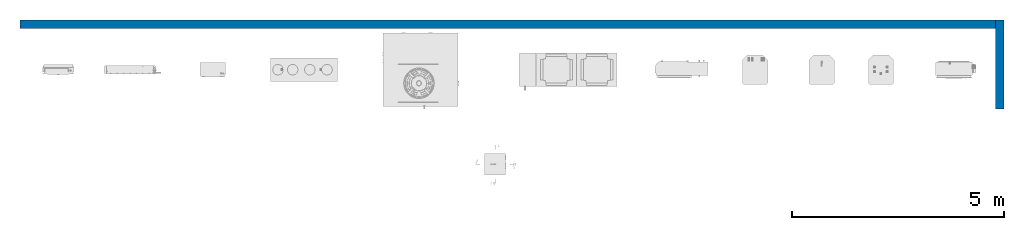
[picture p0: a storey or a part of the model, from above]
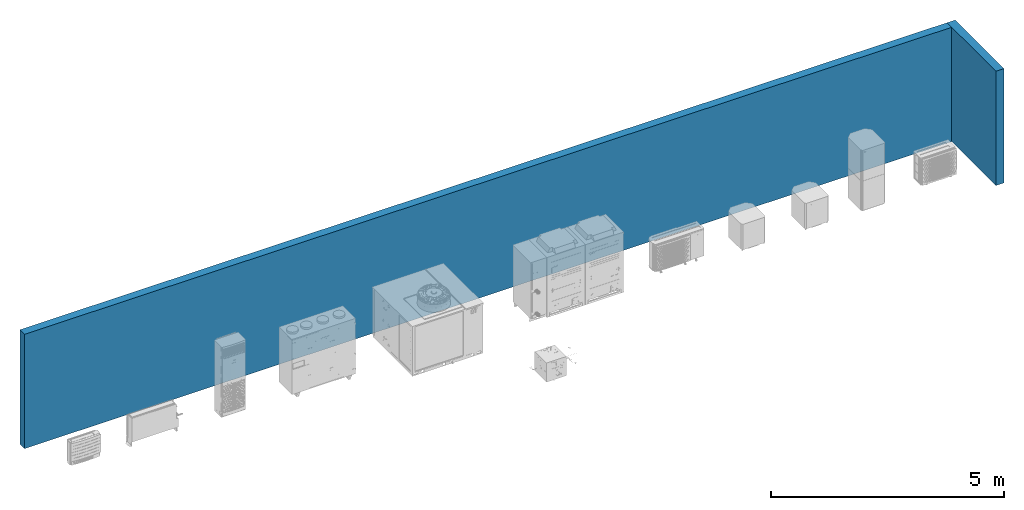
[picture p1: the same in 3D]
Properties of the parts of a building model (IFC2X3), part 1 of 2

# File
Description: ViewDefinition [CoordinationView_V2.0]
Time: 2023-03-29T12:23:34
Written by: The EXPRESS Data Manager Version 5.02.0100.07 : 28 Aug 2013
Made in: 20220224_1700(x64) - Exporter 19.2.60.3 - Default UI
Comment: STEP Physical File produced by: The EXPRESS Data Manager Version 5.02.0100.07 : 28 Aug 2013 * Module: EDMstepFileFactory/EDMstandAlone * Creation date: Wed Mar 29 12:23:34 2023 * Host: DESKTOP-IHH7OF8 * Database: C:\Users\BMP_02\AppData\Local\Temp\{1E1F3719-2578-4ED5-A2A8-9CAE0F05E7C7}\ifc * Database version: 5507 * Database creation date: Wed Mar 29 12:23:26 2023 * Schema: IFC2X3 * Model: DataRepository.ifc * Model creation date: Wed Mar 29 12:23:28 2023 * Header model: DataRepository.ifc_HeaderModel * Header model creation date: Wed Mar 29 12:23:28 2023 * EDMuser: sdai-user * EDMgroup: sdai-group * License ID and type: 5605 : Permanent license. Expiry date: * EDMstepFileFactory options: 020000

# IfcSite, Default
RefLatitude: 42, 24, 53, 508911; RefLongitude: -71, -15, -29, -58837; RefElevation: 0 mm
Other - Category: Project Information

# IfcBuilding
Pset_BuildingCommon - NumberOfStoreys: 1
Other - Category: Project Information

# IfcBuildingStorey, Level 1
LongName: Level 1; Elevation: 0 mm
Other(Type) - Category: Levels; Family Name: Level
Identity Data(Type) - Type Name: Level 1
Graphics(Type) - Color: 0; Line Pattern: Solid; Line Weight: 1; Symbol at End 1 Default: no; Symbol at End 2 Default: yes
Constraints(Type) - Elevation Base: Project Base Point
Constraints - Elevation: 0 mm
Dimensions - Computation Height: 0 mm
Identity Data - Structural: no; Building Story: yes; Name: Level 1
Other - Category: Levels; Family: Level: Level 1; Family and Type: Level: Level 1; Type: Level: Level 1; Type Id: Level: Level 1

# IfcBuildingElementProxy: reference geometry_gen, RSen_00_GM_FB_reference geometry_gen_witas:reference geometry_gen:1430872
In: Level 1
Type - Material: RSen_x_rgb 255 128 128 T80 red_gen, RSen_x_rgb 255 0 0 T00 red_gen, RSen_x_rgb 255 255 255 T00 pure white_gen, RSen_x_rgb 000 000 000 T00 black_gen, RSen_x_rgb 021 107 182 T00 blue_gen, RSen_x_rgb 000 128 000 T80 green_gen
Type - Constraints - Default Elevation: 0 mm; WT_H Reference_angled wall mounted: angled wall mounted_gen; WT_H Reference_parallel wall mounted: parallel wall mounted_gen; WT_H Reference_pendant - horizontal mounted: pendant - horizontal mounted_gen; WT_H Reference_pendant - vertical mounted: pendant - vertical mounted_gen; WT_H Reference_recessed: recessed_gen; WT_H Reference_wall mounted: wall mounted_gen
Type - Identity Data - Type Name: reference geometry_gen; WT_I Coding: V4.0; WT_I Interface: V4.0
Type - Other - Category: Generic Models; Family Name: RSen_00_GM_FB_reference geometry_gen_witas
Type - Text - 250: 250 mm; WT_I Revit manual: http://revit-mep-be-localiser.blogspot.com/2010/01/referentiebalk.html
Pset_BuildingElementProxyCommon - Reference: reference geometry_gen
Constraints - Elevation: 0 mm; Level: Level: Level 1; Host: Level : Level 1; WT_H Depth 1: 500 mm; WT_H Depth 2: 10000 mm; WT_H Half height: 250 mm; WT_H Half height_negative: -250 mm; WT_H Half length: 250 mm; WT_H Half length_negative: -250 mm; WT_H Height: 500 mm; WT_H Length: 500 mm; WT_H Reference_type: wall mounted_gen; WT_H Suspension: no; WT_H Suspension_height: 0 mm; WT_H X coordinate in plane: 0 mm; WT_H Y coordinate in plane: 0 mm
Construction - WT_V Angled wall mounted: no; WT_V Parallel wall mounted: no; WT_V Pendant - horizontal mounted: no; WT_V Pendant - vertical mounted: no; WT_V Plane: 1; WT_V Recess depth: 0 mm; WT_V Recessed: no; WT_V Rotation about axis: 0 deg; WT_V Surface mounted: yes; WT_V Suspension_height: 0 mm; WT_V X coordinate in plane: 0 mm; WT_V Y coordinate in plane: 0 mm; WT_V Z coordinate in plane: 0.1 mm
Dimensions - Area: 2.52812 m2; Volume: 0.375224 m3
Graphics - Mark: no
Other - Schedule Level: Level: Level 1; Family: RSen_00_GM_FB_reference geometry_gen_witas: reference geometry_gen; Family and Type: RSen_00_GM_FB_reference geometry_gen_witas: reference geometry_gen; Type: RSen_00_GM_FB_reference geometry_gen_witas: reference geometry_gen; Type Id: RSen_00_GM_FB_reference geometry_gen_witas: reference geometry_gen
Phasing - Phase Created: New Construction
Text - Dim_01: L; Dim_02: H; Dim_03: W

# IfcBuildingElementProxy: standard, RSen_57_ME_FB_SOg - uatyq20abay1 - SH_daikin_tbq:standard:1710730
In: Level 1
Type - Material: RSen_n6_PE_black, RSen_x_rgb 202 196 176 T00 silk gray_gen, RSen_x_rgb 055 053 053 T00 gray_gen, RSen_x_rgb 000 163 228 T00 blue_gen, RSen_x_rgb 079 201 245 T00 blue_gen, RSen_x_rgb 0 0 0 T30 aluminium rectangular canvas_gen
Type - Constraints - Default Elevation: 0 mm; TBQ SOg: yes
Type - Dimensions - TBQ Height: 1600 mm; TBQ Length: 1790 mm; TBQ Width: 1730 mm
Type - Identity Data - Manufacturer: Daikin Europe N.V.; Type Name: standard
Type - Materials and Finishes - TBQ Material 01: RSen_x_rgb 202 196 176 T00 silk gray_gen; TBQ Material 02: RSen_n6_PE_black; TBQ Material 03: RSen_x_rgb 0 0 0 T30 aluminium rectangular canvas_gen
Type - Other - Category: Mechanical Equipment; Family Name: RSen_57_ME_FB_SOg - uatyq20abay1 - SH_daikin_tbq
Pset_BuildingElementProxyCommon - Reference: standard
Pset_ManufacturerTypeInformation - Manufacturer: Daikin Europe N.V.
Constraints - Moves With Nearby Elements: no
Dimensions - Area: 14.7374 m2; Volume: 3.49974 m3
Identity Data - Mark: 110
Other - Family: RSen_57_ME_FB_SOg - uatyq20abay1 - SH_daikin_tbq: standard; Family and Type: RSen_57_ME_FB_SOg - uatyq20abay1 - SH_daikin_tbq: standard; Type: RSen_57_ME_FB_SOg - uatyq20abay1 - SH_daikin_tbq: standard; Type Id: RSen_57_ME_FB_SOg - uatyq20abay1 - SH_daikin_tbq: standard
Phasing - Phase Created: New Construction

# IfcBuildingElementProxy: standard, RSen_55_ME_FB_SOg - ewya008d2v3p - SH_daikin_tbq:standard:1500545
In: Level 1
Type - Material: RSen_x_rgb 000 163 228 T00 blue_gen, RSen_x_rgb 079 201 245 T00 blue_gen, RSen_x_rgb 055 053 053 T00 gray_gen, RSen_x_rgb 195 195 195 T00 silver_gen, RSen_x_rgb 255 255 255 T00 pure white_gen
Type - Constraints - Default Elevation: 1219.2 mm; TBQ SOg: yes
Type - Dimensions - TBQ Height: 770 mm; TBQ Length: 1245 mm; TBQ Width: 396 mm
Type - Identity Data - Manufacturer: Daikin Europe N.V.; Type Name: standard
Type - Materials and Finishes - TBQ Material 01: RSen_x_rgb 255 255 255 T00 pure white_gen; TBQ Material 02: RSen_x_rgb 195 195 195 T00 silver_gen
Type - Other - Category: Mechanical Equipment; Family Name: RSen_55_ME_FB_SOg - ewya008d2v3p - SH_daikin_tbq
Pset_BuildingElementProxyCommon - Reference: standard
Pset_ManufacturerTypeInformation - Manufacturer: Daikin Europe N.V.
Constraints - Moves With Nearby Elements: no
Dimensions - Area: 3.1003 m2; Volume: 0.285794 m3
Identity Data - Mark: 102
Other - Family: RSen_55_ME_FB_SOg - ewya008d2v3p - SH_daikin_tbq: standard; Family and Type: RSen_55_ME_FB_SOg - ewya008d2v3p - SH_daikin_tbq: standard; Type: RSen_55_ME_FB_SOg - ewya008d2v3p - SH_daikin_tbq: standard; Type Id: RSen_55_ME_FB_SOg - ewya008d2v3p - SH_daikin_tbq: standard
Phasing - Phase Created: New Construction

# IfcBuildingElementProxy: standard, RSen_55_ME_FB_SOg - ewyq050bawn - service panel hydro module - SH_daikin_tbq:standard:1500450
In: Level 1
Type - Material: RSen_x_rgb 000 163 228 T00 blue_gen, RSen_x_rgb 079 201 245 T00 blue_gen, RSen_x_rgb 055 053 053 T00 gray_gen, RSen_x_rgb 202 196 176 T00 silk gray_gen
Type - Constraints - Default Elevation: 1219.2 mm; TBQ SOg: yes
Type - Construction - TBQ Isolator switch_width: 48 mm
Type - Dimensions - TBQ Depth: 780 mm; TBQ Height: 1578 mm; TBQ Width: 448 mm
Type - Identity Data - Manufacturer: Daikin Europe N.V.; Type Name: standard
Type - Materials and Finishes - TBQ Material: RSen_x_rgb 202 196 176 T00 silk gray_gen
Type - Other - Category: Mechanical Equipment; Family Name: RSen_55_ME_FB_SOg - ewyq050bawn - service panel hydro module - SH_daikin_tbq
Pset_BuildingElementProxyCommon - Reference: standard
Pset_ManufacturerTypeInformation - Manufacturer: Daikin Europe N.V.
Constraints - Moves With Nearby Elements: no
Dimensions - Area: 2.51164 m2; Volume: 0.459061 m3
Identity Data - Mark: 99
Other - Family: RSen_55_ME_FB_SOg - ewyq050bawn - service panel hydro module - SH_daikin_tbq: standard; Family and Type: RSen_55_ME_FB_SOg - ewyq050bawn - service panel hydro module - SH_daikin_tbq: standard; Type: RSen_55_ME_FB_SOg - ewyq050bawn - service panel hydro module - SH_daikin_tbq: standard; Type Id: RSen_55_ME_FB_SOg - ewyq050bawn - service panel hydro module - SH_daikin_tbq: standard
Phasing - Phase Created: New Construction

# IfcBuildingElementProxy: standard (2)
In: Level 1
Type - Material: RSen_x_rgb 000 163 228 T00 blue_gen, RSen_x_rgb 079 201 245 T00 blue_gen, RSen_x_rgb 055 053 053 T00 gray_gen, RSen_x_rgb 202 196 176 T00 silk gray_gen, RSen_x_rgb 0 0 0 T30 aluminium rectangular canvas_gen
Type - Constraints - Default Elevation: 1219.2 mm; TBQ SOg: yes
Type - Dimensions - TBQ Depth: 780 mm; TBQ Height: 1684 mm; TBQ Width: 955 mm
Type - Identity Data - Manufacturer: Daikin Europe N.V.; Type Name: standard
Type - Materials and Finishes - TBQ Material 01: RSen_x_rgb 202 196 176 T00 silk gray_gen; TBQ Material 02: RSen_x_rgb 0 0 0 T30 aluminium rectangular canvas_gen
Type - Other - Category: Mechanical Equipment; Family Name: RSen_55_ME_FB_SOg - ewyq050bawn - service panel outdoor module - SH_daikin_tbq
Pset_BuildingElementProxyCommon - Reference: standard
Pset_ManufacturerTypeInformation - Manufacturer: Daikin Europe N.V.
Constraints - Moves With Nearby Elements: no
Dimensions - Area: 7.72265 m2; Volume: 0.180782 m3
Other - Family: RSen_55_ME_FB_SOg - ewyq050bawn - service panel outdoor module - SH_daikin_tbq: standard; Family and Type: RSen_55_ME_FB_SOg - ewyq050bawn - service panel outdoor module - SH_daikin_tbq: standard; Type: RSen_55_ME_FB_SOg - ewyq050bawn - service panel outdoor module - SH_daikin_tbq: standard; Type Id: RSen_55_ME_FB_SOg - ewyq050bawn - service panel outdoor module - SH_daikin_tbq: standard
Phasing - Phase Created: New Construction
Name (RSen_55_ME_FB_SOg - ewyq050bawn - service panel outdoor module - SH_daikin_tbq:standard:...) | Mark
1500451 | 100
1500452 | 101

# IfcBuildingElementProxy: standard, RSen_53_ME_FB_SOg - hxhd125a8v1b - SH_daikin_tbq:standard:1431638
In: Level 1
Type - Material: RSen_x_rgb 000 163 228 T00 blue_gen, RSen_x_rgb 079 201 245 T00 blue_gen, RSen_x_rgb 055 053 053 T00 gray_gen, RSen_x_rgb 224 223 219 T00 stainless steel_gen
Type - Constraints - Default Elevation: 1219.2 mm; TBQ SOg: yes
Type - Dimensions - TBQ Height: 708 mm; TBQ Length: 600 mm; TBQ Width: 694 mm
Type - Identity Data - Manufacturer: Daikin Europe N.V.; Type Name: standard
Type - Materials and Finishes - TBQ Material 01: RSen_x_rgb 224 223 219 T00 stainless steel_gen; TBQ Material 02: RSen_x_rgb 055 053 053 T00 gray_gen
Type - Other - Category: Mechanical Equipment; Family Name: RSen_53_ME_FB_SOg - hxhd125a8v1b - SH_daikin_tbq
Pset_BuildingElementProxyCommon - Reference: standard
Pset_ManufacturerTypeInformation - Manufacturer: Daikin Europe N.V.
Constraints - Moves With Nearby Elements: no; Host: Level : Level 1
Dimensions - Area: 2.24688 m2; Volume: 0.278093 m3
Identity Data - Mark: 93
Other - Family: RSen_53_ME_FB_SOg - hxhd125a8v1b - SH_daikin_tbq: standard; Family and Type: RSen_53_ME_FB_SOg - hxhd125a8v1b - SH_daikin_tbq: standard; Type: RSen_53_ME_FB_SOg - hxhd125a8v1b - SH_daikin_tbq: standard; Type Id: RSen_53_ME_FB_SOg - hxhd125a8v1b - SH_daikin_tbq: standard
Phasing - Phase Created: New Construction

# IfcBuildingElementProxy: standard, RSen_55_ME_FB_SOg - ekhbrd016ady17 - SH_daikin_tbq:standard:2643349
In: Level 1
Type - Material: RSen_x_rgb 000 163 228 T00 blue_gen, RSen_x_rgb 079 201 245 T00 blue_gen, RSen_x_rgb 055 053 053 T00 gray_gen, RSen_x_rgb 224 223 219 T00 stainless steel_gen
Type - Constraints - Default Elevation: 1219.2 mm; TBQ SOg: yes
Type - Dimensions - TBQ Height: 708 mm; TBQ Length: 600 mm; TBQ Width: 694 mm
Type - Identity Data - Manufacturer: Daikin Europe N.V.; Type Name: standard
Type - Materials and Finishes - TBQ Material 01: RSen_x_rgb 224 223 219 T00 stainless steel_gen; TBQ Material 02: RSen_x_rgb 055 053 053 T00 gray_gen
Type - Other - Category: Mechanical Equipment; Family Name: RSen_55_ME_FB_SOg - ekhbrd016ady17 - SH_daikin_tbq
Pset_BuildingElementProxyCommon - Reference: standard
Pset_ManufacturerTypeInformation - Manufacturer: Daikin Europe N.V.
Constraints - Moves With Nearby Elements: no
Dimensions - Area: 2.24688 m2; Volume: 0.278093 m3
Identity Data - Mark: 163
Other - Family: RSen_55_ME_FB_SOg - ekhbrd016ady17 - SH_daikin_tbq: standard; Family and Type: RSen_55_ME_FB_SOg - ekhbrd016ady17 - SH_daikin_tbq: standard; Type: RSen_55_ME_FB_SOg - ekhbrd016ady17 - SH_daikin_tbq: standard; Type Id: RSen_55_ME_FB_SOg - ekhbrd016ady17 - SH_daikin_tbq: standard
Phasing - Phase Created: New Construction

# IfcBuildingElementProxy: standard, RSen_53_ME_FB_SOg - ekhtsu260ac - SH_daikin_tbq:standard:1431418
In: Level 1
Type - Material: RSen_x_rgb 000 163 228 T00 blue_gen, RSen_x_rgb 079 201 245 T00 blue_gen, RSen_x_rgb 055 053 053 T00 gray_gen, RSen_x_rgb 224 223 219 T00 stainless steel_gen
Type - Constraints - Default Elevation: 1219.2 mm; TBQ SOg: yes
Type - Identity Data - Manufacturer: Daikin Europe N.V.; Type Name: standard
Type - Other - Category: Mechanical Equipment; Family Name: RSen_53_ME_FB_SOg - ekhtsu260ac - SH_daikin_tbq
Pset_BuildingElementProxyCommon - Reference: standard
Pset_ManufacturerTypeInformation - Manufacturer: Daikin Europe N.V.
Constraints - Moves With Nearby Elements: no
Dimensions - Area: 8.64187 m2; TBQ Height: 1610 mm; TBQ Length: 600 mm; TBQ Width: 694 mm; Volume: 0.537493 m3
Identity Data - Mark: 91
Materials and Finishes - TBQ Material: RSen_x_rgb 224 223 219 T00 stainless steel_gen
Other - Family: RSen_53_ME_FB_SOg - ekhtsu260ac - SH_daikin_tbq: standard; Family and Type: RSen_53_ME_FB_SOg - ekhtsu260ac - SH_daikin_tbq: standard; Type: RSen_53_ME_FB_SOg - ekhtsu260ac - SH_daikin_tbq: standard; Type Id: RSen_53_ME_FB_SOg - ekhtsu260ac - SH_daikin_tbq: standard
Phasing - Phase Created: New Construction

# IfcBuildingElementProxy: standard, RSen_57_ME_FB_SOg - atb03rasnadbt00 - SH_daikin_tbq:standard:1750596
In: Level 1
Type - Material: RSen_x_rgb 000 163 228 T00 blue_gen, RSen_x_rgb 079 201 245 T00 blue_gen, RSen_x_rgb 055 053 053 T00 gray_gen, RSen_x_rgb 255 255 255 T00 pure white_gen, RSen_x_rgb 197 197 197 T00 chrome steel_gen, RSen_x_rgb 000 000 000 T00 black_gen
Type - Constraints - Default Elevation: 1219.2 mm; TBQ SOg: yes
Type - Dimensions - TBQ Height: 1550 mm; TBQ Length: 1580 mm; TBQ Width: 550 mm
Type - Identity Data - Manufacturer: Daikin Europe N.V.; Type Name: standard
Type - Materials and Finishes - TBQ Material 01: RSen_x_rgb 255 255 255 T00 pure white_gen; TBQ Material 02: RSen_x_rgb 000 000 000 T00 black_gen; TBQ Material 03: RSen_x_rgb 197 197 197 T00 chrome steel_gen
Type - Other - Category: Mechanical Equipment; Family Name: RSen_57_ME_FB_SOg - atb03rasnadbt00 - SH_daikin_tbq
Pset_BuildingElementProxyCommon - Reference: standard
Pset_ManufacturerTypeInformation - Manufacturer: Daikin Europe N.V.
Constraints - Moves With Nearby Elements: no
Dimensions - Area: 9.99702 m2; Volume: 1.25806 m3
Identity Data - Mark: 114
Other - Family: RSen_57_ME_FB_SOg - atb03rasnadbt00 - SH_daikin_tbq: standard; Family and Type: RSen_57_ME_FB_SOg - atb03rasnadbt00 - SH_daikin_tbq: standard; Type: RSen_57_ME_FB_SOg - atb03rasnadbt00 - SH_daikin_tbq: standard; Type Id: RSen_57_ME_FB_SOg - atb03rasnadbt00 - SH_daikin_tbq: standard
Phasing - Phase Created: New Construction

# IfcBuildingElementProxy: standard, RSen_55_ME_FB_SOg - ava125amve - SH_daikin_tbq:standard:2095876
In: Level 1
Type - Material: RSen_x_rgb 055 053 053 T00 gray_gen, RSen_x_rgb 249 249 249 T00 white_gen, RSen_n6_PE_black
Type - Constraints - Default Elevation: 1219.2 mm; TBQ SOg: yes
Type - Dimensions - TBQ Height: 350 mm; TBQ Length: 598 mm; TBQ Width: 1850 mm
Type - Identity Data - Manufacturer: Daikin Europe N.V.; Type Name: standard
Type - Materials and Finishes - TBQ Material 01: RSen_x_rgb 249 249 249 T00 white_gen; TBQ Material 02: RSen_n6_PE_black
Type - Other - Category: Mechanical Equipment; Family Name: RSen_55_ME_FB_SOg - ava125amve - SH_daikin_tbq
Pset_BuildingElementProxyCommon - Reference: standard
Pset_ManufacturerTypeInformation - Manufacturer: Daikin Europe N.V.
Constraints - Moves With Nearby Elements: no
Dimensions - Area: 4.40059 m2; Volume: 0.363839 m3
Identity Data - Mark: 128
Other - Family: RSen_55_ME_FB_SOg - ava125amve - SH_daikin_tbq: standard; Family and Type: RSen_55_ME_FB_SOg - ava125amve - SH_daikin_tbq: standard; Type: RSen_55_ME_FB_SOg - ava125amve - SH_daikin_tbq: standard; Type Id: RSen_55_ME_FB_SOg - ava125amve - SH_daikin_tbq: standard
Phasing - Phase Created: New Construction

# IfcBuildingElementProxy: standard, RSen_55_ME_FB_SOg - fvxm50a3v1b9 - SH_daikin_tbq:standard:2339185
In: Level 1
Type - Material: RSen_x_rgb 055 053 053 T00 gray_gen, RSen_x_rgb 255 255 255 T00 pure white_gen
Type - Constraints - Default Elevation: 1219.2 mm; TBQ SOg: yes
Type - Identity Data - Manufacturer: Daikin Europe N.V.; Type Name: standard
Type - Other - Category: Mechanical Equipment; Family Name: RSen_55_ME_FB_SOg - fvxm50a3v1b9 - SH_daikin_tbq
Pset_BuildingElementProxyCommon - Reference: standard
Pset_ManufacturerTypeInformation - Manufacturer: Daikin Europe N.V.
Constraints - Moves With Nearby Elements: no
Dimensions - Area: 1.72482 m2; TBQ Height: 600 mm; TBQ Length: 750 mm; TBQ Width: 238 mm; Volume: 0.0955584 m3
Identity Data - Mark: 146
Materials and Finishes - TBQ Material 01: RSen_x_rgb 255 255 255 T00 pure white_gen; TBQ Material 02: RSen_x_rgb 0 0 0 T30 aluminium rectangular canvas_gen
Other - Family: RSen_55_ME_FB_SOg - fvxm50a3v1b9 - SH_daikin_tbq: standard; Family and Type: RSen_55_ME_FB_SOg - fvxm50a3v1b9 - SH_daikin_tbq: standard; Type: RSen_55_ME_FB_SOg - fvxm50a3v1b9 - SH_daikin_tbq: standard; Type Id: RSen_55_ME_FB_SOg - fvxm50a3v1b9 - SH_daikin_tbq: standard
Phasing - Phase Created: New Construction

# IfcBuildingElementProxy: standard, RSen_55_ME_FB_SOg - fna60a2veb9 - SH_daikin_tbq:standard:2294291
In: Level 1
Type - Material: RSen_x_rgb 156 169 164 T00 Galvanised steel_gen, RSen_x_rgb 40 40 40 T00 canvas_gen
Type - Constraints - Default Elevation: 1219.2 mm; TBQ SOg: yes
Type - Dimensions - TBQ Height: 723 mm; TBQ Length: 1190 mm; TBQ Width: 200 mm
Type - Identity Data - Manufacturer: Daikin Europe N.V.; Type Name: standard
Type - Materials and Finishes - TBQ Material_01: RSen_x_rgb 156 169 164 T00 Galvanised steel_gen; TBQ Material_02: RSen_x_rgb 40 40 40 T00 canvas_gen
Type - Other - Category: Mechanical Equipment; Family Name: RSen_55_ME_FB_SOg - fna60a2veb9 - SH_daikin_tbq
Pset_BuildingElementProxyCommon - Reference: standard
Pset_ManufacturerTypeInformation - Manufacturer: Daikin Europe N.V.
Constraints - Moves With Nearby Elements: no
Dimensions - Area: 1.90891 m2; Volume: 0.138914 m3
Identity Data - Mark: 138
Other - Family: RSen_55_ME_FB_SOg - fna60a2veb9 - SH_daikin_tbq: standard; Family and Type: RSen_55_ME_FB_SOg - fna60a2veb9 - SH_daikin_tbq: standard; Type: RSen_55_ME_FB_SOg - fna60a2veb9 - SH_daikin_tbq: standard; Type Id: RSen_55_ME_FB_SOg - fna60a2veb9 - SH_daikin_tbq: standard
Phasing - Phase Created: New Construction

# IfcBuildingElementProxy: standard, RSen_55_ME_FB_SOg - 5mxm90a2v1b9 - SH_daikin_tbq:standard:1451970
In: Level 1
Type - Material: RSen_x_rgb 255 255 255 T00 pure white_gen
Type - Constraints - Default Elevation: 1219.2 mm; TBQ SOg: yes
Type - Dimensions - TBQ Height: 734 mm; TBQ Length: 958 mm; TBQ Width: 408 mm
Type - Identity Data - Manufacturer: Daikin Europe N.V.; Type Name: standard
Type - Materials and Finishes - TBQ Material 01: RSen_x_rgb 255 255 255 T00 pure white_gen; TBQ Material 02: RSen_x_rgb 255 255 255 T00 pure white_gen
Type - Other - Category: Mechanical Equipment; Family Name: RSen_55_ME_FB_SOg - 5mxm90a2v1b9 - SH_daikin_tbq
Pset_BuildingElementProxyCommon - Reference: standard
Pset_ManufacturerTypeInformation - Manufacturer: Daikin Europe N.V.
Constraints - Moves With Nearby Elements: no
Dimensions - Area: 3.20005 m2; Volume: 0.182351 m3
Identity Data - Mark: 94
Other - Family: RSen_55_ME_FB_SOg - 5mxm90a2v1b9 - SH_daikin_tbq: standard; Family and Type: RSen_55_ME_FB_SOg - 5mxm90a2v1b9 - SH_daikin_tbq: standard; Type: RSen_55_ME_FB_SOg - 5mxm90a2v1b9 - SH_daikin_tbq: standard; Type Id: RSen_55_ME_FB_SOg - 5mxm90a2v1b9 - SH_daikin_tbq: standard
Phasing - Phase Created: New Construction

# IfcEnergyConversionDevice: 5mxm90a2v1b9 - split_daikin_5mxm-a9, RSen_55_ME_FB_outdoor unit - split - 5 rooms_daikin:5mxm90a2v1b9 - split_daikin_5mxm-a9:1430869
In: Level 1
Type - PredefinedType: SPLITSYSTEM; Material: RSen_x_rgb 255 255 255 T00 pure white_gen
Type - Constraints - Default Elevation: 0 mm
Type - Construction - TBQen_C_diameter_type: OD; TBQen_C_diameter_type_index: 1; TBQen_C_SOg_ME_01: RSen_55_ME_FB_SOg - 5mxm90a2v1b9 - SH_daikin_tbq: standard; TBQen_C_SOg_ME_02: standard
Type - Dimensions - TBQ_I Spacing_default: 0 mm; TBQ_I Spacing_minimum: 0 mm
Type - Electrical - RSen_E_c01_apparent_power: 0 W; RSen_E_c01_current: 0 A; RSen_E_c01_division_engine: no; RSen_E_c01_load_class: Other; RSen_E_c01_number_of_poles: 1; RSen_E_c01_voltage: 230 V; TBQen_E_c01_power: 0 W; TBQen_E_c01_power_factor: 1
Type - Electrical - Loads - RSen_E_c01_apparent_power_phase_1: 0 W; RSen_E_c01_apparent_power_phase_2: 0 W; RSen_E_c01_apparent_power_phase_3: 0 W
Type - Identity Data - Description: Heat Pump; Manufacturer: Daikin Europe N.V.; Model: Split; OmniClass Number: 23.75.10.17.17.17; OmniClass Title: Heat Pumps, Heating-Cooling Function; RSen_C_code_article: 5MXM90A2V1B9; RSen_C_code_product_class: 5MXM-A9; RSen_C_content_creator: © ThorbiQ; RSen_C_content_date_changed: 14/01/2021; RSen_C_content_date_issue: 14/01/2021; RSen_C_content_provider: Daikin Europe N.V.; RSen_C_content_version: 2.0.0; RSen_C_description: Heat Pump; RSen_C_model: Split; RSen_C_revit_version: 2018; RSen_C_type: Multi model application; RSen_C_type_comments: Outdoor unit; TBQ_I BaseKeynote: -; TBQen_C_code_product: 5MXM90A9; TBQen_C_IFC_version: 2x3; TBQen_C_license: Creative Commons Attribution NoDerivs (CC-ND); TBQen_C_license_info: https://tldrlegal.com/license/creative-commons-attribution-noderivs-(cc-nd)#summary; Type Comments: Outdoor unit; Type Name: 5mxm90a2v1b9 - split_daikin_5mxm-a9; URL: www.daikineurope.com
Type - Materials and Finishes - RSen_C_material: RSen_x_rgb 255 255 255 T00 pure white_gen
Type - Mechanical - RSen_P_c11_load_value: 0
Type - Model Properties - TBQen_C_mounting_ceiling: no; TBQen_C_mounting_floor: yes; TBQen_C_mounting_wall: no
Type - Other - Category: Mechanical Equipment; Family Name: RSen_55_ME_FB_outdoor unit - split - 5 rooms_daikin; RSen_E_c01_description: c01_el; RSen_E_c02_description: c02_controls; RSen_P_c01_description: c01_liquid pipe_room A; RSen_P_c01_diameter: 6.4 mm; RSen_P_c02_description: c02_gas pipe_room A; RSen_P_c02_diameter: 9.52 mm; RSen_P_c03_description: c03_liquid pipe_room B; RSen_P_c03_diameter: 6.4 mm; RSen_P_c04_description: c04_gas pipe_room B; RSen_P_c04_diameter: 9.52 mm; RSen_P_c05_description: c05_liquid pipe_room C; RSen_P_c05_diameter: 6.4 mm; RSen_P_c06_description: c06_gas pipe_room C; RSen_P_c06_diameter: 12.7 mm; RSen_P_c07_description: c07_liquid pipe_room D; RSen_P_c07_diameter: 6.4 mm; RSen_P_c08_description: c08_gas pipe_room D; RSen_P_c08_diameter: 12.7 mm; RSen_P_c09_description: c09_liquid pipe_room E; RSen_P_c09_diameter: 6.4 mm; RSen_P_c10_description: c10_gas pipe_room E; RSen_P_c10_diameter: 15.9 mm; RSen_P_c11_description: c11_drain; RSen_P_c11_diameter: 18 mm; TBQen_E_c01_power_factor_state: Lagging; TBQen_E_c01_system_type: Power - Unbalanced; TBQen_E_c01_yes_no: yes; TBQen_E_c02_yes_no: yes; TBQen_P_c01_diameter_calc: 6.4 mm; TBQen_P_c01_flow_configuration: Calculated; TBQen_P_c01_flow_direction: Out; TBQen_P_c01_loss_method: Not Defined; TBQen_P_c01_system_classification: Hydronic Supply; TBQen_P_c01_yes_no: yes; TBQen_P_c02_diameter_calc: 9.5 mm; TBQen_P_c02_flow_configuration: Calculated; TBQen_P_c02_flow_direction: In; TBQen_P_c02_loss_method: Not Defined; TBQen_P_c02_system_classification: Hydronic Return; TBQen_P_c02_yes_no: yes; TBQen_P_c03_diameter_calc: 6.4 mm; TBQen_P_c03_flow_configuration: Calculated; TBQen_P_c03_flow_direction: Out; TBQen_P_c03_loss_method: Not Defined; TBQen_P_c03_system_classification: Hydronic Supply; TBQen_P_c03_yes_no: yes; TBQen_P_c04_diameter_calc: 9.5 mm; TBQen_P_c04_flow_configuration: Calculated; TBQen_P_c04_flow_direction: In; TBQen_P_c04_loss_method: Not Defined; TBQen_P_c04_system_classification: Hydronic Return; TBQen_P_c04_yes_no: yes; TBQen_P_c05_diameter_calc: 6.4 mm; TBQen_P_c05_flow_configuration: Calculated; TBQen_P_c05_flow_direction: Out; TBQen_P_c05_loss_method: Not Defined; TBQen_P_c05_system_classification: Hydronic Supply; TBQen_P_c05_yes_no: yes; TBQen_P_c06_diameter_calc: 12.7 mm; TBQen_P_c06_flow_configuration: Calculated; TBQen_P_c06_flow_direction: In; TBQen_P_c06_loss_method: Not Defined; TBQen_P_c06_system_classification: Hydronic Return; TBQen_P_c06_yes_no: yes; TBQen_P_c07_diameter_calc: 6.4 mm; TBQen_P_c07_flow_configuration: Calculated; TBQen_P_c07_flow_direction: Out; TBQen_P_c07_loss_method: Not Defined; TBQen_P_c07_system_classification: Hydronic Supply; TBQen_P_c07_yes_no: yes; TBQen_P_c08_diameter_calc: 12.7 mm; TBQen_P_c08_flow_configuration: Calculated; TBQen_P_c08_flow_direction: In; TBQen_P_c08_loss_method: Not Defined; TBQen_P_c08_system_classification: Hydronic Return; TBQen_P_c08_yes_no: yes; TBQen_P_c09_diameter_calc: 6.4 mm; TBQen_P_c09_flow_configuration: Calculated; TBQen_P_c09_flow_direction: Out; TBQen_P_c09_loss_method: Not Defined; TBQen_P_c09_system_classification: Hydronic Supply; TBQen_P_c09_yes_no: yes; TBQen_P_c10_diameter_calc: 15.9 mm; TBQen_P_c10_flow_configuration: Calculated; TBQen_P_c10_flow_direction: In; TBQen_P_c10_loss_method: Not Defined; TBQen_P_c10_system_classification: Hydronic Return; TBQen_P_c10_yes_no: yes; TBQen_P_c11_diameter_calc: 18 mm; TBQen_P_c11_flow_configuration: Fixture Units; TBQen_P_c11_flow_direction: Out; TBQen_P_c11_loss_method: Not Defined; TBQen_P_c11_system_classification: Sanitary; TBQen_P_c11_yes_no: yes
Pset_ManufacturerTypeInformation - Manufacturer: Daikin Europe N.V.
Pset_DistributionFlowElementCommon - Reference: 5mxm90a2v1b9 - split_daikin_5mxm-a9
Constraints - Elevation: 0 mm; Host: Level : Level 1; Level: Level: Level 1
Construction - RSen_C_mounting: On the floor; TBQen_C_alignment: Center; TBQen_C_alignment_index: 0; TBQen_C_component_02_offset: 0 mm; TBQen_C_component_03_offset: 0 mm; TBQen_C_component_04_offset: 0 mm; TBQen_C_GOg: no; TBQen_C_mounting_index: 0; TBQen_C_offset_from_base_level: 0 mm; TBQen_C_offset_from_wall: 0 mm; TBQen_C_placement: Spacing Default; TBQen_C_placement_index: 0; TBQen_C_SOg: yes
Dimensions - Area: 38.3842 m2; RSen_C_height: 734 mm; RSen_C_length: 959 mm; RSen_C_width: 391 mm; Volume: 8.07687 m3
Graphics - TBQen_C_clearance_zone: no; TBQen_C_connection_zone: no; TBQen_C_logo: no; TBQen_C_maintenance_zone: no; TBQen_C_neighbour_unit: no; TBQen_C_neighbour_unit_displacement_back: 0 mm; TBQen_C_neighbour_unit_displacement_front: 0 mm; TBQen_C_neighbour_unit_displacement_left: 0 mm; TBQen_C_neighbour_unit_displacement_right: 0 mm
Identity Data - Mark: 84
Mechanical - RSen_P_c01_volume_flow: 0 m3/s; RSen_P_c02_volume_flow: 0 m3/s; RSen_P_c03_volume_flow: 0 m3/s; RSen_P_c04_volume_flow: 0 m3/s; RSen_P_c05_volume_flow: 0 m3/s; RSen_P_c06_volume_flow: 0 m3/s; RSen_P_c07_volume_flow: 0 m3/s; RSen_P_c08_volume_flow: 0 m3/s; RSen_P_c09_volume_flow: 0 m3/s; RSen_P_c10_volume_flow: 0 m3/s; System Classification: Hydronic Supply,Hydronic Return,Power,Hydronic Supply,Hydronic Return,Hydronic Supply,Controls,Hydronic Supply,Hydronic Return,Hydronic Supply,Hydronic Return,Sanitary
Other - Family: RSen_55_ME_FB_outdoor unit - split - 5 rooms_daikin: 5mxm90a2v1b9 - split_daikin_5mxm-a9; Family and Type: RSen_55_ME_FB_outdoor unit - split - 5 rooms_daikin: 5mxm90a2v1b9 - split_daikin_5mxm-a9; Schedule Level: Level: Level 1; Type: RSen_55_ME_FB_outdoor unit - split - 5 rooms_daikin: 5mxm90a2v1b9 - split_daikin_5mxm-a9; Type Id: RSen_55_ME_FB_outdoor unit - split - 5 rooms_daikin: 5mxm90a2v1b9 - split_daikin_5mxm-a9; ZZZ_V P_c01_plane_Integer: 4; ZZZ_V P_c01_X_Length: -407.5 mm; ZZZ_V P_c01_Y_Length: 49 mm
Phasing - Phase Created: New Construction
Text - RSen_C_content_manual: https://thorbiq.freshdesk.com/support/solutions

# IfcEnergyConversionDevice: atb03rasnadbt00 - air handling unit - right_daikin_lxwxh 1580x550x1550 mm, RSen_57_ME_FB_air handling unit - modular - t_daikin:atb03rasnadbt00 - air handling unit - right_daikin_lxwxh 1580x550x1550 mm:1747841
In: Level 1
Type - PredefinedType: AIRHANDLER; Classification: 57.10.10.10 (Uniformat); Material: RSen_x_rgb 255 255 255 T00 pure white_gen
Type - Constraints - Default Elevation: 0 mm
Type - Construction - TBQen_C_diameter_type_index: 1; TBQen_C_SOg_ME_02: standard; TBQen_C_diameter_type: OD; TBQen_C_SOg_ME_01: RSen_57_ME_FB_SOg - atb03rasnadbt00 - SH_daikin_tbq: standard
Type - Dimensions - RSen_C_height: 1550 mm; RSen_C_length: 1580 mm; RSen_C_width: 550 mm
Type - Electrical - RSen_E_c01_division_engine: no; RSen_E_c01_load_class: Other; RSen_E_c01_number_of_poles: 1; TBQen_E_c01_power_factor: 1; RSen_E_c01_apparent_power: 1060 W; RSen_E_c01_current: 0 A; RSen_E_c01_voltage: 230 V; TBQen_E_c01_power: 1060 W
Type - Identity Data - Assembly Code: 57.10.10.10; Description: Ventilation; Manufacturer: Daikin Europe N.V.; Model: Modular T; OmniClass Number: 23.75.35.14; OmniClass Title: Air Handling Units; RSen_C_code_article: ATB03RASNADBT00; RSen_C_code_ETIM: Ventilation appliance; RSen_C_code_ETIM_URL: https://prod.etim-international.com/Class/Details?classId=EC000267&classVersion=5; RSen_C_code_gtin: -; RSen_C_code_product_class: ATB-S; RSen_C_content_creator: © ThorbiQ; RSen_C_content_date_changed: 14/01/2021; RSen_C_content_date_issue: 14/01/2021; RSen_C_content_provider: Daikin Europe N.V.; RSen_C_content_version: 2.0.0; RSen_C_description: Ventilation; RSen_C_model: Modular T; RSen_C_revit_version: 2018; RSen_C_type: Air handling unit - right; RSen_C_type_comments: Indoor Unit; TBQ_I BaseKeynote: 57.10.10.10; TBQen_C_code_product: ATB03RAS; TBQen_C_IFC_version: 2x3; TBQen_C_license: Creative Commons Attribution NoDerivs (CC-ND); TBQen_C_license_info: https://tldrlegal.com/license/creative-commons-attribution-noderivs-(cc-nd)#summary; Type Comments: Indoor Unit; Type Name: atb03rasnadbt00 - air handling unit - right_daikin_lxwxh 1580x550x1550 mm; URL: www.daikineurope.com
Type - Materials and Finishes - RSen_C_material: RSen_x_rgb 255 255 255 T00 pure white_gen
Type - Mechanical - RSen_P_c01_load_value: 0; RSen_P_c02_load_value: 0; TBQ_I Air flow rate_speed 1: 7.8477 m3/s; TBQ_I Air flow rate_speed 2: 0 m3/s; TBQ_I Air flow rate_speed 3: 0 m3/s
Type - Model Properties - TBQen_C_mounting_ceiling: no; TBQen_C_mounting_floor: yes; TBQen_C_mounting_wall: no
Type - Other - Category: Mechanical Equipment; TBQen_E_c01_yes_no: yes; TBQen_E_c02_yes_no: yes; TBQen_P_c01_yes_no: yes; TBQen_P_c02_yes_no: yes; TBQen_M_c01_yes_no: yes; TBQen_M_c02_yes_no: yes; Family Name: RSen_57_ME_FB_air handling unit - modular - t_daikin; RSen_E_c01_description: c01_el; RSen_E_c02_description: c02_controls; RSen_M_c01_description: c01_fresh air_outdoor; RSen_M_c01_diameter: 250 mm; RSen_M_c01_height: 0 mm; RSen_M_c01_width: 0 mm; RSen_M_c02_description: c02_exhaust air; RSen_M_c02_diameter: 250 mm; RSen_M_c02_height: 0 mm; RSen_M_c02_width: 0 mm; RSen_M_c03_description: c03_supply air; RSen_M_c03_diameter: 250 mm; RSen_M_c03_height: 0 mm; RSen_M_c03_width: 0 mm; RSen_M_c04_description: c04_return air; RSen_M_c04_diameter: 250 mm; RSen_M_c04_height: 0 mm; RSen_M_c04_width: 0 mm; RSen_P_c01_description: c01_drain piping connection; RSen_P_c01_diameter: 21.3 mm; RSen_P_c02_description: c01_drain piping connection; RSen_P_c02_diameter: 21.3 mm; TBQen_E_c01_power_factor_state: Lagging; TBQen_E_c01_system_type: Power - Balanced; TBQen_M_c01_flow_configuration: Preset; TBQen_M_c01_flow_direction: In; TBQen_M_c01_loss_method: Not Defined; TBQen_M_c01_shape: Round; TBQen_M_c01_system_classification: Supply Air; TBQen_M_c02_flow_configuration: Preset; TBQen_M_c02_flow_direction: Out; TBQen_M_c02_loss_method: Not Defined; TBQen_M_c02_shape: Round; TBQen_M_c02_system_classification: Exhaust Air; TBQen_M_c03_flow_configuration: Preset; TBQen_M_c03_flow_direction: Out; TBQen_M_c03_loss_method: Not Defined; TBQen_M_c03_shape: Round; TBQen_M_c03_system_classification: Supply Air; TBQen_M_c03_yes_no: yes; TBQen_M_c04_flow_configuration: Preset; TBQen_M_c04_flow_direction: In; TBQen_M_c04_loss_method: Not Defined; TBQen_M_c04_shape: Round; TBQen_M_c04_system_classification: Return Air; TBQen_M_c04_yes_no: yes; TBQen_P_c01_diameter_calc: 21.3 mm; TBQen_P_c01_flow_configuration: Fixture Units; TBQen_P_c01_flow_direction: Out; TBQen_P_c01_loss_method: Not Defined; TBQen_P_c01_system_classification: Sanitary; TBQen_P_c02_diameter_calc: 21.3 mm; TBQen_P_c02_flow_configuration: Fixture Units; TBQen_P_c02_flow_direction: Out; TBQen_P_c02_loss_method: Not Defined; TBQen_P_c02_system_classification: Sanitary
Pset_ManufacturerTypeInformation - Manufacturer: Daikin Europe N.V.
Pset_DistributionFlowElementCommon - Reference: atb03rasnadbt00 - air handling unit - right_daikin_lxwxh 1580x550x1550 mm
Constraints - Elevation: 0 mm; Level: Level: Level 1; Host: Level : Level 1
Construction - TBQen_C_alignment_index: 0; TBQen_C_GOg: no; TBQen_C_SOg: yes; TBQen_C_suspension_height: 0 mm; TBQen_C_alignment: Center
Dimensions - Area: 88.141 m2; Volume: 28.3056 m3
Graphics - TBQen_C_clearance_zone: no; TBQen_C_connection_zone: no; TBQen_C_logo: no; TBQen_C_maintenance_zone: no; TBQen_C_neighbour_unit: no; TBQen_C_neighbour_unit_displacement_back: 0 mm; TBQen_C_neighbour_unit_displacement_front: 0 mm; TBQen_C_neighbour_unit_displacement_left: 0 mm; TBQen_C_neighbour_unit_displacement_right: 0 mm
Identity Data - Mark: 112
Mechanical - RSen_M_c01_flow_rate: 7.8477 m3/s; RSen_M_c02_flow_rate: 7.8477 m3/s; RSen_M_c03_flow_rate: 7.8477 m3/s; RSen_M_c04_flow_rate: 7.8477 m3/s; System Classification: Sanitary,Return Air,Supply Air,Exhaust Air,Power,Controls
Mechanical - Flow - TBQen_M_flow_rate_index: 0; TBQen_M_flow_rate: 7.8477 m3/s; TBQen_M_flow_rate_info: Low
Other - Schedule Level: Level: Level 1; Family: RSen_57_ME_FB_air handling unit - modular - t_daikin: atb03rasnadbt00 - air handling unit - right_daikin_lxwxh 1580x550x1550 mm; Family and Type: RSen_57_ME_FB_air handling unit - modular - t_daikin: atb03rasnadbt00 - air handling unit - right_daikin_lxwxh 1580x550x1550 mm; Type: RSen_57_ME_FB_air handling unit - modular - t_daikin: atb03rasnadbt00 - air handling unit - right_daikin_lxwxh 1580x550x1550 mm; Type Id: RSen_57_ME_FB_air handling unit - modular - t_daikin: atb03rasnadbt00 - air handling unit - right_daikin_lxwxh 1580x550x1550 mm; ZZZ_V P_c01_plane_Integer: 2; ZZZ_V P_c01_X_Length: 524 mm; ZZZ_V P_c01_Y_Length: 0 mm
Phasing - Phase Created: New Construction
Text - RSen_C_content_manual: https://thorbiq.freshdesk.com/support/solutions

# IfcEnergyConversionDevice: ava125amve - floor standing unit_daikin_lxwxh 600x350x1850 mm, RSen_55_ME_FB_indoor unit - sky air - cassette-wall-floor_daikin:ava125amve - floor standing unit_daikin_lxwxh 600x350x1850 mm:2091445
In: Level 1
Type - PredefinedType: AIRCONDITIONINGUNIT; Material: RSen_x_rgb 255 255 255 T00 pure white_gen
Type - Constraints - Default Elevation: 0 mm
Type - Construction - TBQen_C_diameter_type_index: 1; TBQen_C_SOg_ME_02: standard; TBQen_C_accessory_01_index: 0; TBQen_C_diameter_type: OD; TBQen_C_SOg_ME_01: RSen_55_ME_FB_SOg - ava125amve - SH_daikin_tbq: standard
Type - Dimensions - RSen_C_height: 1850 mm; RSen_C_length: 600 mm; RSen_C_width: 350 mm
Type - Electrical - RSen_E_c01_division_engine: no; RSen_E_c01_load_class: Other; RSen_E_c01_number_of_poles: 1; TBQen_E_c01_power_factor: 1; RSen_E_c01_apparent_power: 0 W; RSen_E_c01_current: 0 A; RSen_E_c01_voltage: 230 V; TBQen_E_c01_power: 0 W
Type - Identity Data - Description: Floor standing; Manufacturer: Daikin Europe N.V.; Model: Sky Air; OmniClass Number: 23.75.10.24.21.27.24; OmniClass Title: Room Air Conditioners; RSen_C_code_article: AVA125AMVE; RSen_C_code_ETIM: Air-conditioning split system – inside unit (evaporator); RSen_C_code_ETIM_URL: https://prod.etim-international.com/Class/Details?classId=EC011580&classVersion=4; RSen_C_code_gtin: -; RSen_C_code_product_class: AVA-A; RSen_C_content_creator: © ThorbiQ; RSen_C_content_date_changed: 14/01/2021; RSen_C_content_date_issue: 14/01/2021; RSen_C_content_provider: Daikin Europe N.V.; RSen_C_content_version: 2.0.0; RSen_C_description: Floor standing; RSen_C_model: Sky Air; RSen_C_revit_version: 2018; RSen_C_type: Floor standing unit; RSen_C_type_comments: Indoor unit; TBQ_I BaseKeynote: 55.10.10.10; TBQen_C_code_product: AVA125A; TBQen_C_IFC_version: 2x3; TBQen_C_license: Creative Commons Attribution NoDerivs (CC-ND); TBQen_C_license_info: https://tldrlegal.com/license/creative-commons-attribution-noderivs-(cc-nd)#summary; Type Comments: Indoor unit; Type Name: ava125amve - floor standing unit_daikin_lxwxh 600x350x1850 mm; URL: www.daikineurope.com
Type - Materials and Finishes - RSen_C_material: RSen_x_rgb 255 255 255 T00 pure white_gen
Type - Mechanical - RSen_P_c01_volume_flow: 0 m3/s; RSen_P_c02_volume_flow: 0 m3/s; RSen_P_c03_load_value: 0; TBQ_I Air flow rate_speed 1: 14.1259 m3/s; TBQ_I Air flow rate_speed 2: 15.303 m3/s; TBQ_I Air flow rate_speed 3: 16.4802 m3/s; TBQ_I Fresh air_percentage intake: 0
Type - Model Properties - TBQen_C_mounting_ceiling: no; TBQen_C_mounting_floor: yes; TBQen_C_mounting_wall: no
Type - Other - Category: Mechanical Equipment; TBQen_E_c01_yes_no: yes; TBQen_E_c02_yes_no: yes; TBQen_P_c01_yes_no: yes; TBQen_P_c02_yes_no: yes; TBQen_P_c03_yes_no: yes; Family Name: RSen_55_ME_FB_indoor unit - sky air - cassette-wall-floor_daikin; RSen_E_c01_description: c01_el; RSen_E_c02_description: c02_controls; RSen_P_c01_description: c02_liquid piping connection; RSen_P_c01_diameter: 9.52 mm; RSen_P_c02_description: c03_gas piping connection; RSen_P_c02_diameter: 15.9 mm; RSen_P_c03_description: c04_drain piping connection; RSen_P_c03_diameter: 26 mm; TBQen_E_c01_power_factor_state: Lagging; TBQen_E_c01_system_type: Power - Balanced; TBQen_P_c01_diameter_calc: 9.5 mm; TBQen_P_c01_flow_configuration: Preset; TBQen_P_c01_flow_direction: In; TBQen_P_c01_loss_method: Not Defined; TBQen_P_c01_system_classification: Hydronic Supply; TBQen_P_c02_diameter_calc: 15.9 mm; TBQen_P_c02_flow_configuration: Preset; TBQen_P_c02_flow_direction: Out; TBQen_P_c02_loss_method: Not Defined; TBQen_P_c02_system_classification: Hydronic Return; TBQen_P_c03_diameter_calc: 26 mm; TBQen_P_c03_flow_configuration: Fixture Units; TBQen_P_c03_flow_direction: Out; TBQen_P_c03_loss_method: Not Defined; TBQen_P_c03_system_classification: Sanitary
Pset_ManufacturerTypeInformation - Manufacturer: Daikin Europe N.V.
Pset_DistributionFlowElementCommon - Reference: ava125amve - floor standing unit_daikin_lxwxh 600x350x1850 mm
Constraints - Elevation: 0 mm; Level: Level: Level 1; Host: Level : Level 1
Construction - TBQen_C_alignment_index: 0; TBQen_C_GOg: no; TBQen_C_SOg: yes; TBQen_C_suspension_height: 0 mm; TBQen_C_alignment: Center
Dimensions - Area: 43.4071 m2; Volume: 9.7773 m3
Graphics - TBQen_C_clearance_zone: no; TBQen_C_connection_zone: no; TBQen_C_logo: no; TBQen_C_maintenance_zone: no; TBQen_C_neighbour_unit: no; TBQen_C_neighbour_unit_displacement_back: 0 mm; TBQen_C_neighbour_unit_displacement_front: 0 mm; TBQen_C_neighbour_unit_displacement_left: 0 mm; TBQen_C_neighbour_unit_displacement_right: 0 mm
Identity Data - Mark: 127
Mechanical - System Classification: Hydronic Return,Hydronic Supply,Sanitary,Power,Controls
Mechanical - Flow - TBQen_M_flow_rate: 15.303 m3/s; TBQen_M_flow_rate_index: 1; TBQen_M_flow_rate_info: Norm.
Other - Schedule Level: Level: Level 1; ZZZ_V P_c01_plane_Integer: 2; Family: RSen_55_ME_FB_indoor unit - sky air - cassette-wall-floor_daikin: ava125amve - floor standing unit_daikin_lxwxh 600x350x1850 mm; Family and Type: RSen_55_ME_FB_indoor unit - sky air - cassette-wall-floor_daikin: ava125amve - floor standing unit_daikin_lxwxh 600x350x1850 mm; Type: RSen_55_ME_FB_indoor unit - sky air - cassette-wall-floor_daikin: ava125amve - floor standing unit_daikin_lxwxh 600x350x1850 mm; Type Id: RSen_55_ME_FB_indoor unit - sky air - cassette-wall-floor_daikin: ava125amve - floor standing unit_daikin_lxwxh 600x350x1850 mm; ZZZ_V P_c01_X_Length: -223 mm; ZZZ_V P_c01_Y_Length: -91 mm
Phasing - Phase Created: New Construction
Text - RSen_C_content_manual: https://thorbiq.freshdesk.com/support/solutions

# IfcEnergyConversionDevice: ekhbrd016ady17 - altherma high temperature_daikin_lxwxh 600x694x708 mm, RSen_53_ME_FB_indoor unit - altherma - air to water - wall mounted_daikin:ekhbrd016ady17 - altherma high temperature_daikin_lxwxh 600x694x708 mm:2641016
In: Level 1
Type - PredefinedType: AIRCONDITIONINGUNIT; Classification: 56.10.10 (Uniformat); Material: RSen_x_rgb 188 188 190 T00 gray_gen
Type - Constraints - Default Elevation: 0 mm
Type - Construction - TBQen_C_diameter_type_index: 1; TBQen_C_SOg_ME_02: standard; TBQen_C_accessory_01_index: 0; TBQen_C_diameter_type: OD; TBQen_C_SOg_ME_01: RSen_55_ME_FB_SOg - ekhbrd016ady17 - SH_daikin_tbq: standard
Type - Dimensions - RSen_C_diameter: 0 mm; RSen_C_height: 708 mm; RSen_C_length: 600 mm; RSen_C_width: 694 mm
Type - Electrical - RSen_E_c01_load_class: Other; TBQen_E_c01_power_factor: 1; RSen_E_c01_division_engine: yes; RSen_E_c01_number_of_poles: 3; RSen_E_c01_apparent_power: 0 W; RSen_E_c01_current: 0 A; RSen_E_c01_voltage: 400 V; TBQen_E_c01_power: 0 W
Type - Identity Data - Assembly Code: 56.10.10; Description: Air To Water Heat Pump; Manufacturer: Daikin Europe N.V.; Model: Altherma High temperature; OmniClass Number: 23.75.10.21.11; OmniClass Title: Air-Source Heat Pumps; RSen_C_code_article: EKHBRD016ADY17; RSen_C_code_product_class: EKHBRD-ADY17; RSen_C_content_creator: © ThorbiQ; RSen_C_content_date_changed: 14/01/2021; RSen_C_content_date_issue: 14/01/2021; RSen_C_content_provider: Daikin Europe N.V.; RSen_C_content_version: 2.0.0; RSen_C_description: Air To Water Heat Pump; RSen_C_model: Altherma High temperature; RSen_C_revit_version: 2018; RSen_C_type: Heating Only; RSen_C_type_comments: Indoor Unit; TBQ_I BaseKeynote: 56.10.10; TBQen_C_code_product: EKHBRD016ADY17; TBQen_C_data_issue_date: RSen_53_ME_FB_indoor unit - altherma - bivalent_daikin; TBQen_C_IFC_version: 2x3; TBQen_C_license: Creative Commons Attribution NoDerivs (CC-ND); TBQen_C_license_info: https://tldrlegal.com/license/creative-commons-attribution-noderivs-(cc-nd)#summary; Type Comments: Indoor Unit; Type Name: ekhbrd016ady17 - altherma high temperature_daikin_lxwxh 600x694x708 mm; URL: www.daikineurope.com
Type - Materials and Finishes - RSen_C_material: RSen_x_rgb 188 188 190 T00 gray_gen
Type - Model Properties - TBQen_C_mounting_ceiling: no; TBQen_C_mounting_floor: yes; TBQen_C_mounting_wall: no
Type - Other - Category: Mechanical Equipment; TBQen_E_c01_yes_no: yes; TBQen_E_c02_yes_no: yes; TBQen_P_c01_yes_no: yes; TBQen_P_c02_yes_no: yes; TBQen_P_c03_yes_no: yes; TBQen_P_c04_yes_no: yes; Family Name: RSen_53_ME_FB_indoor unit - altherma - air to water - wall mounted_daikin; RSen_E_c01_description: c01_el; RSen_E_c02_description: c02_controls; RSen_P_c01_description: c01_liquid connection; RSen_P_c01_diameter: 9.52 mm; RSen_P_c02_description: c02_gas connection; RSen_P_c02_diameter: 15.9 mm; RSen_P_c03_description: c03_heating in; RSen_P_c03_diameter: 25 mm; RSen_P_c04_description: c04_heating out; RSen_P_c04_diameter: 25 mm; TBQen_E_c01_power_factor_state: Lagging; TBQen_E_c01_system_type: Power - Balanced; TBQen_P_c01_diameter_calc: 9.5 mm; TBQen_P_c01_flow_configuration: Preset; TBQen_P_c01_flow_direction: In; TBQen_P_c01_loss_method: Not Defined; TBQen_P_c01_system_classification: Hydronic Supply; TBQen_P_c02_diameter_calc: 15.9 mm; TBQen_P_c02_flow_configuration: Preset; TBQen_P_c02_flow_direction: Out; TBQen_P_c02_loss_method: Not Defined; TBQen_P_c02_system_classification: Hydronic Return; TBQen_P_c03_diameter_calc: 25 mm; TBQen_P_c03_flow_configuration: Calculated; TBQen_P_c03_flow_direction: In; TBQen_P_c03_loss_method: Not Defined; TBQen_P_c03_system_classification: Hydronic Return; TBQen_P_c04_diameter_calc: 25 mm; TBQen_P_c04_flow_configuration: Calculated; TBQen_P_c04_flow_direction: Out; TBQen_P_c04_loss_method: Not Defined; TBQen_P_c04_system_classification: Hydronic Supply
Pset_ManufacturerTypeInformation - Manufacturer: Daikin Europe N.V.
Pset_DistributionFlowElementCommon - Reference: ekhbrd016ady17 - altherma high temperature_daikin_lxwxh 600x694x708 mm
Constraints - Elevation: 0 mm; Level: Level: Level 1; Host: Level : Level 1
Construction - TBQen_C_alignment_index: 0; TBQen_C_GOg: no; TBQen_C_offset_from_base_level: 0 mm; TBQen_C_SOg: yes; TBQen_C_suspension_height: 0 mm; TBQen_C_alignment: Center
Dimensions - Area: 29.6784 m2; Volume: 7.32096 m3
Graphics - TBQen_C_clearance_zone: no; TBQen_C_connection_zone: no; TBQen_C_logo: no; TBQen_C_maintenance_zone: no; TBQen_C_neighbour_unit: no; TBQen_C_neighbour_unit_displacement_back: 0 mm; TBQen_C_neighbour_unit_displacement_front: 0 mm; TBQen_C_neighbour_unit_displacement_left: 0 mm; TBQen_C_neighbour_unit_displacement_right: 0 mm
Identity Data - Mark: 162
Mechanical - RSen_P_c01_volume_flow: 0 m3/s; RSen_P_c02_volume_flow: 0 m3/s; RSen_P_c03_volume_flow: 0 m3/s; RSen_P_c04_volume_flow: 0 m3/s; System Classification: Hydronic Supply,Hydronic Return,Power,Controls,Hydronic Supply
Other - Schedule Level: Level: Level 1; ZZZ_V P_c01_plane_Integer: 4; Family: RSen_53_ME_FB_indoor unit - altherma - air to water - wall mounted_daikin: ekhbrd016ady17 - altherma high temperature_daikin_lxwxh 600x694x708 mm; Family and Type: RSen_53_ME_FB_indoor unit - altherma - air to water - wall mounted_daikin: ekhbrd016ady17 - altherma high temperature_daikin_lxwxh 600x694x708 mm; Type: RSen_53_ME_FB_indoor unit - altherma - air to water - wall mounted_daikin: ekhbrd016ady17 - altherma high temperature_daikin_lxwxh 600x694x708 mm; Type Id: RSen_53_ME_FB_indoor unit - altherma - air to water - wall mounted_daikin: ekhbrd016ady17 - altherma high temperature_daikin_lxwxh 600x694x708 mm; ZZZ_V P_c01_X_Length: 0 mm; ZZZ_V P_c01_Y_Length: 268 mm
Phasing - Phase Created: New Construction
Text - RSen_C_content_manual: https://thorbiq.freshdesk.com/support/solutions

# IfcEnergyConversionDevice: ewya008d2v3p - heat pump_daikin_ewya-dv3p, RSen_55_ME_FB_air cooled chiller_daikin:ewya008d2v3p - heat pump_daikin_ewya-dv3p:1489211
In: Level 1
Type - PredefinedType: AIRCOOLED; Classification: 55.10.10 (Uniformat); Material: RSen_x_rgb 255 255 255 T00 pure white_gen
Type - Constraints - Default Elevation: 1000 mm
Type - Construction - TBQen_C_SOg_ME_02: standard; TBQen_C_diameter_type: DN; TBQen_C_diameter_type_index: 0; TBQen_C_SOg_ME_01: RSen_55_ME_FB_SOg - ewya008d2v3p - SH_daikin_tbq: standard
Type - Dimensions - TBQ_I Spacing_default: 0 mm; TBQ_I Spacing_minimum: 0 mm
Type - Electrical - RSen_E_c01_division_engine: no; RSen_E_c01_load_class: Other; RSen_E_c01_number_of_poles: 1; TBQen_E_c01_power_factor: 1; RSen_E_c01_apparent_power: 1190 W; RSen_E_c01_current: 0 A; RSen_E_c01_voltage: 230 V; TBQen_E_c01_power: 1190 W
Type - Electrical - Loads - RSen_E_c01_apparent_power_phase_1: 396.667 W; RSen_E_c01_apparent_power_phase_2: 396.667 W; RSen_E_c01_apparent_power_phase_3: 396.667 W
Type - Identity Data - Assembly Code: 55.10.10; Description: Heat Pump; Manufacturer: Daikin Europe N.V.; Model: Chillers air cooled; OmniClass Number: 23.75.10.24.21.21; OmniClass Title: Packaged Water Chillers; RSen_C_code_article: EWYA008D2V3P; RSen_C_code_ETIM: Airco splitsysteem - multi split condensingunit luchtgekoeld; RSen_C_code_ETIM_URL: https://prod.etim-international.com/Class/Details?classId=EC011584&classVersion=2; RSen_C_code_product_class: EWYA-DV3P; RSen_C_content_creator: © ThorbiQ; RSen_C_content_date_changed: 14/01/2021; RSen_C_content_date_issue: 14/01/2021; RSen_C_content_provider: Daikin Europe N.V.; RSen_C_content_version: 2.0.0; RSen_C_description: Heat Pump; RSen_C_model: Chillers air cooled; RSen_C_revit_version: 2018; RSen_C_type: Air cooled mini inverter heat pump; RSen_C_type_comments: Single Unit; TBQ_I BaseKeynote: 55.10.10; TBQen_C_code_product: EWYA008DV3P; TBQen_C_IFC_version: 2x3; TBQen_C_license: Creative Commons Attribution NoDerivs (CC-ND); TBQen_C_license_info: https://tldrlegal.com/license/creative-commons-attribution-noderivs-(cc-nd)#summary; Type Comments: Single Unit; Type Name: ewya008d2v3p - heat pump_daikin_ewya-dv3p; URL: www.daikineurope.com
Type - Materials and Finishes - RSen_C_material: RSen_x_rgb 255 255 255 T00 pure white_gen
Type - Model Properties - TBQen_C_mounting_ceiling: no; TBQen_C_mounting_floor: yes; TBQen_C_mounting_wall: no
Type - Other - Category: Mechanical Equipment; TBQen_E_c01_yes_no: yes; TBQen_E_c02_yes_no: yes; TBQen_P_c01_yes_no: yes; TBQen_P_c02_yes_no: yes; Family Name: RSen_55_ME_FB_air cooled chiller_daikin; RSen_E_c01_description: c01_el; RSen_E_c02_description: c02_controls; RSen_P_c01_description: c01_chilled water in connection; RSen_P_c01_diameter: 25 mm; RSen_P_c02_description: c02_chilled water out connection; RSen_P_c02_diameter: 25 mm; TBQen_E_c01_power_factor_state: Lagging; TBQen_E_c01_system_type: Power - Unbalanced; TBQen_P_c01_diameter_calc: 25 mm; TBQen_P_c01_flow_configuration: Calculated; TBQen_P_c01_flow_direction: In; TBQen_P_c01_loss_method: Not Defined; TBQen_P_c01_system_classification: Hydronic Return; TBQen_P_c02_diameter_calc: 25 mm; TBQen_P_c02_flow_configuration: Preset; TBQen_P_c02_flow_direction: Out; TBQen_P_c02_loss_method: Not Defined; TBQen_P_c02_system_classification: Hydronic Supply
Pset_ManufacturerTypeInformation - Manufacturer: Daikin Europe N.V.
Pset_DistributionFlowElementCommon - Reference: ewya008d2v3p - heat pump_daikin_ewya-dv3p
Constraints - Elevation: 0 mm; Level: Level: Level 1; Host: Level : Level 1
Construction - TBQen_C_alignment_index: 0; TBQen_C_component_02_offset: 0 mm; TBQen_C_component_03_offset: 0 mm; TBQen_C_component_04_offset: 0 mm; TBQen_C_GOg: no; TBQen_C_offset_from_base_level: 0 mm; TBQen_C_placement_index: 0; TBQen_C_SOg: yes; TBQen_C_alignment: Center; TBQen_C_placement: Spacing Default
Dimensions - Area: 33.3114 m2; RSen_C_height: 770 mm; RSen_C_length: 1245 mm; RSen_C_width: 396 mm; Volume: 7.98508 m3
Graphics - TBQen_C_clearance_zone: no; TBQen_C_connection_zone: no; TBQen_C_logo: no; TBQen_C_maintenance_zone: no; TBQen_C_neighbour_unit: no; TBQen_C_neighbour_unit_displacement_back: 0 mm; TBQen_C_neighbour_unit_displacement_front: 0 mm; TBQen_C_neighbour_unit_displacement_left: 0 mm; TBQen_C_neighbour_unit_displacement_right: 0 mm
Identity Data - Mark: 96
Mechanical - RSen_P_c01_volume_flow: 0 m3/s; RSen_P_c02_volume_flow: 0 m3/s; System Classification: Hydronic Return,Power,Hydronic Supply,Communication
Other - Schedule Level: Level: Level 1; ZZZ_V P_c01_plane_Integer: 4; Family: RSen_55_ME_FB_air cooled chiller_daikin: ewya008d2v3p - heat pump_daikin_ewya-dv3p; Family and Type: RSen_55_ME_FB_air cooled chiller_daikin: ewya008d2v3p - heat pump_daikin_ewya-dv3p; Type: RSen_55_ME_FB_air cooled chiller_daikin: ewya008d2v3p - heat pump_daikin_ewya-dv3p; Type Id: RSen_55_ME_FB_air cooled chiller_daikin: ewya008d2v3p - heat pump_daikin_ewya-dv3p; ZZZ_V P_c01_X_Length: -412 mm; ZZZ_V P_c01_Y_Length: -288 mm
Phasing - Phase Created: New Construction
Text - RSen_C_content_manual: https://thorbiq.freshdesk.com/support/solutions

# IfcEnergyConversionDevice: ewyq050bawn - heat pump_daikin_ewyq-bawn, RSen_55_ME_FB_air cooled chiller_daikin:ewyq050bawn - heat pump_daikin_ewyq-bawn:1489272
In: Level 1
Type - PredefinedType: AIRCOOLED; Classification: 55.10.10 (Uniformat); Material: RSen_x_rgb 255 255 255 T00 pure white_gen
Type - Constraints - Default Elevation: 1000 mm
Type - Construction - TBQen_C_SOg_ME_02: standard; TBQen_C_diameter_type_index: 0; TBQen_C_diameter_type: DN; TBQen_C_SOg_ME_01: RSen_55_ME_FB_SOg - ewyq050bawn - SH_daikin_tbq: standard
Type - Dimensions - TBQ_I Spacing_default: 0 mm; TBQ_I Spacing_minimum: 0 mm
Type - Electrical - RSen_E_c01_division_engine: no; RSen_E_c01_load_class: Other; TBQen_E_c01_power_factor: 1; RSen_E_c01_apparent_power: 19840 W; RSen_E_c01_current: 49.6 A; RSen_E_c01_number_of_poles: 3; RSen_E_c01_voltage: 400 V; TBQen_E_c01_power: 18800 W
Type - Electrical - Loads - RSen_E_c01_apparent_power_phase_1: 6613.33 W; RSen_E_c01_apparent_power_phase_2: 6613.33 W; RSen_E_c01_apparent_power_phase_3: 6613.33 W
Type - Identity Data - Assembly Code: 55.10.10; Description: Heat Pump; Manufacturer: Daikin Europe N.V.; Model: Chillers air cooled; OmniClass Number: 23.75.10.24.21.21; OmniClass Title: Packaged Water Chillers; RSen_C_code_article: EWYQ050BAWN; RSen_C_code_ETIM: Airco splitsysteem - multi split condensingunit luchtgekoeld; RSen_C_code_ETIM_URL: https://prod.etim-international.com/Class/Details?classId=EC011584&classVersion=2; RSen_C_code_product_class: EWYQ-BAWN; RSen_C_content_creator: © ThorbiQ; RSen_C_content_date_changed: 14/01/2021; RSen_C_content_date_issue: 14/01/2021; RSen_C_content_provider: Daikin Europe N.V.; RSen_C_content_version: 2.0.0; RSen_C_description: Heat Pump; RSen_C_model: Chillers air cooled; RSen_C_revit_version: 2018; RSen_C_type: Air cooled scroll inverter heat pump; RSen_C_type_comments: Single Unit; TBQ_I BaseKeynote: 55.10.10; TBQen_C_code_product: EWYQ050BAWN; TBQen_C_IFC_version: 2x3; TBQen_C_license: Creative Commons Attribution NoDerivs (CC-ND); TBQen_C_license_info: https://tldrlegal.com/license/creative-commons-attribution-noderivs-(cc-nd)#summary; Type Comments: Single Unit; Type Name: ewyq050bawn - heat pump_daikin_ewyq-bawn; URL: www.daikineurope.com
Type - Materials and Finishes - RSen_C_material: RSen_x_rgb 255 255 255 T00 pure white_gen
Type - Model Properties - TBQen_C_mounting_ceiling: no; TBQen_C_mounting_floor: yes; TBQen_C_mounting_wall: no
Type - Other - Category: Mechanical Equipment; TBQen_E_c01_yes_no: yes; TBQen_E_c02_yes_no: yes; TBQen_P_c01_yes_no: yes; TBQen_P_c02_yes_no: yes; Family Name: RSen_55_ME_FB_air cooled chiller_daikin; RSen_E_c01_description: c01_el; RSen_E_c02_description: c02_controls; RSen_P_c01_description: c01_chilled water in connection; RSen_P_c01_diameter: 50 mm; RSen_P_c02_description: c02_chilled water out connection; RSen_P_c02_diameter: 50 mm; TBQen_E_c01_power_factor_state: Lagging; TBQen_E_c01_system_type: Power - Unbalanced; TBQen_P_c01_diameter_calc: 50 mm; TBQen_P_c01_flow_configuration: Calculated; TBQen_P_c01_flow_direction: In; TBQen_P_c01_loss_method: Not Defined; TBQen_P_c01_system_classification: Hydronic Return; TBQen_P_c02_diameter_calc: 50 mm; TBQen_P_c02_flow_configuration: Preset; TBQen_P_c02_flow_direction: Out; TBQen_P_c02_loss_method: Not Defined; TBQen_P_c02_system_classification: Hydronic Supply
Pset_ManufacturerTypeInformation - Manufacturer: Daikin Europe N.V.
Pset_DistributionFlowElementCommon - Reference: ewyq050bawn - heat pump_daikin_ewyq-bawn
Constraints - Elevation: 0 mm; Level: Level: Level 1; Host: Level : Level 1
Construction - TBQen_C_alignment_index: 0; TBQen_C_component_02_offset: 0 mm; TBQen_C_component_03_offset: 0 mm; TBQen_C_component_04_offset: 0 mm; TBQen_C_GOg: no; TBQen_C_offset_from_base_level: 0 mm; TBQen_C_placement_index: 0; TBQen_C_SOg: yes; TBQen_C_alignment: Center; TBQen_C_placement: Spacing Default
Dimensions - Area: 103.345 m2; RSen_C_height: 1684 mm; RSen_C_length: 2358 mm; RSen_C_width: 780 mm; Volume: 45.1796 m3
Graphics - TBQen_C_clearance_zone: no; TBQen_C_connection_zone: no; TBQen_C_logo: no; TBQen_C_maintenance_zone: no; TBQen_C_neighbour_unit: no; TBQen_C_neighbour_unit_displacement_back: 0 mm; TBQen_C_neighbour_unit_displacement_front: 0 mm; TBQen_C_neighbour_unit_displacement_left: 0 mm; TBQen_C_neighbour_unit_displacement_right: 0 mm
Identity Data - Mark: 97
Mechanical - RSen_P_c01_volume_flow: 0 m3/s; RSen_P_c02_volume_flow: 0 m3/s; System Classification: Hydronic Return,Power,Hydronic Supply,Communication
Other - Schedule Level: Level: Level 1; Family: RSen_55_ME_FB_air cooled chiller_daikin: ewyq050bawn - heat pump_daikin_ewyq-bawn; Family and Type: RSen_55_ME_FB_air cooled chiller_daikin: ewyq050bawn - heat pump_daikin_ewyq-bawn; Type: RSen_55_ME_FB_air cooled chiller_daikin: ewyq050bawn - heat pump_daikin_ewyq-bawn; Type Id: RSen_55_ME_FB_air cooled chiller_daikin: ewyq050bawn - heat pump_daikin_ewyq-bawn; ZZZ_V P_c01_plane_Integer: 3; ZZZ_V P_c01_X_Length: -41 mm; ZZZ_V P_c01_Y_Length: -565.5 mm
Phasing - Phase Created: New Construction
Text - RSen_C_content_manual: https://thorbiq.freshdesk.com/support/solutions

# IfcEnergyConversionDevice: fna60a2veb9 - concealed floor standing unit_daikin_lxwxh 1190x200x720 mm, RSen_55_ME_FB_indoor unit - sky air - concealed ceiling-floor_daikin:fna60a2veb9 - concealed floor standing unit_daikin_lxwxh 1190x200x720 mm:2294110
In: Level 1
Type - PredefinedType: AIRCONDITIONINGUNIT; Material: RSen_x_rgb 255 255 255 T00 pure white_gen
Type - Constraints - Default Elevation: 0 mm
Type - Construction - TBQen_C_diameter_type_index: 1; TBQen_C_SOg_ME_02: standard; TBQen_C_accessory_01_index: 0; TBQen_C_diameter_type: OD; TBQen_C_SOg_ME_01: RSen_55_ME_FB_SOg - fna60a2veb9 - SH_daikin_tbq: standard
Type - Dimensions - RSen_C_height: 720 mm; RSen_C_length: 1190 mm; RSen_C_width: 200 mm
Type - Electrical - RSen_E_c01_division_engine: no; RSen_E_c01_load_class: Other; RSen_E_c01_number_of_poles: 1; TBQen_E_c01_power_factor: 1; RSen_E_c01_apparent_power: 0 W; RSen_E_c01_current: 0 A; RSen_E_c01_voltage: 230 V; TBQen_E_c01_power: 0 W
Type - Identity Data - Description: Floor standing; Manufacturer: Daikin Europe N.V.; Model: Sky Air; OmniClass Number: 23.75.10.24.21.27.24; OmniClass Title: Room Air Conditioners; RSen_C_code_article: FNA60A2VEB9; RSen_C_code_ETIM: Air-conditioning split system – inside unit (evaporator); RSen_C_code_ETIM_URL: https://prod.etim-international.com/Class/Details?classId=EC011580&classVersion=4; RSen_C_code_gtin: -; RSen_C_code_product_class: FNA-A9; RSen_C_content_creator: © ThorbiQ; RSen_C_content_date_changed: 14/01/2021; RSen_C_content_date_issue: 14/01/2021; RSen_C_content_provider: Daikin Europe N.V.; RSen_C_content_version: 2.0.0; RSen_C_description: Floor standing; RSen_C_model: Sky Air; RSen_C_revit_version: 2018; RSen_C_type: Concealed floor standing unit; RSen_C_type_comments: Indoor unit; TBQ_I BaseKeynote: 55.10.10.10; TBQen_C_code_product: FNA60A9; TBQen_C_IFC_version: 2x3; TBQen_C_license: Creative Commons Attribution NoDerivs (CC-ND); TBQen_C_license_info: https://tldrlegal.com/license/creative-commons-attribution-noderivs-(cc-nd)#summary; Type Comments: Indoor unit; Type Name: fna60a2veb9 - concealed floor standing unit_daikin_lxwxh 1190x200x720 mm; URL: www.daikineurope.com
Type - Materials and Finishes - RSen_C_material: RSen_x_rgb 255 255 255 T00 pure white_gen
Type - Mechanical - RSen_P_c03_load_value: 0; TBQ_I Fresh air_percentage intake: 0; RSen_P_c01_volume_flow: 0 m3/s; RSen_P_c02_volume_flow: 0 m3/s; TBQ_I Air flow rate_speed 1: 7.9458 m3/s; TBQ_I Air flow rate_speed 2: 8.71095 m3/s; TBQ_I Air flow rate_speed 3: 9.41724 m3/s
Type - Model Properties - TBQen_C_mounting_ceiling: no; TBQen_C_mounting_floor: yes; TBQen_C_mounting_wall: no
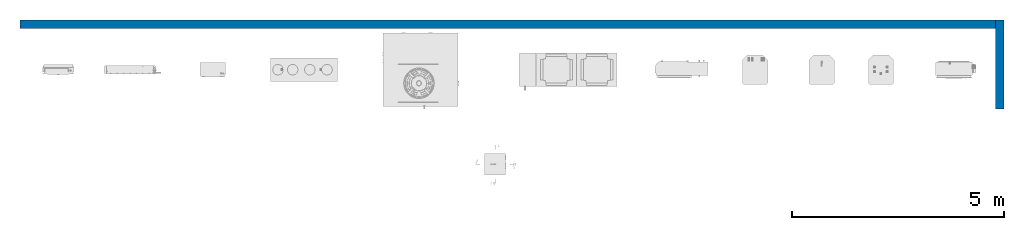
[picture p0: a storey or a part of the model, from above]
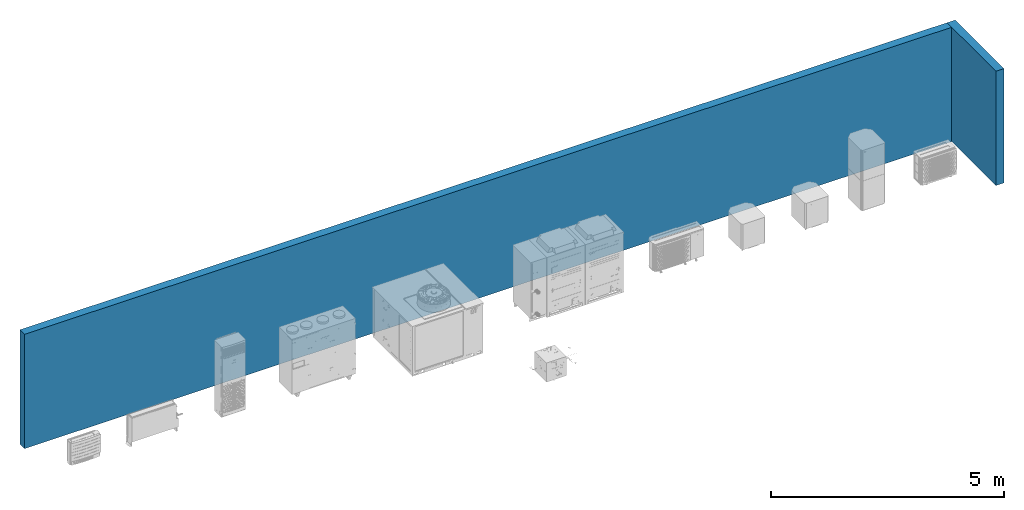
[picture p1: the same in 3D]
Properties of the parts of a building model (IFC2X3), part 2 of 2

# IfcEnergyConversionDevice: fna60a2veb9 - concealed floor standing unit_daikin_lxwxh 1190x200x720 mm, RSen_55_ME_FB_indoor unit - sky air - concealed ceiling-floor_daikin:fna60a2veb9 - concealed floor standing unit_daikin_lxwxh 1190x200x720 mm:2294110
Type - Other - Category: Mechanical Equipment; TBQen_E_c01_yes_no: yes; TBQen_E_c02_yes_no: yes; TBQen_P_c01_yes_no: yes; TBQen_P_c02_yes_no: yes; TBQen_P_c03_yes_no: yes; RSen_M_c01_diameter: 0 mm; RSen_M_c02_diameter: 0 mm; TBQen_M_c01_optional: no; TBQen_M_c01_yes_no: yes; TBQen_M_c02_optional: no; TBQen_M_c02_yes_no: yes; Family Name: RSen_55_ME_FB_indoor unit - sky air - concealed ceiling-floor_daikin; RSen_E_c01_description: c01_el; RSen_E_c02_description: c02_controls; RSen_M_c01_description: c05_return air; RSen_M_c01_height: 1 mm; RSen_M_c01_width: 1 mm; RSen_M_c02_description: c06_supply air; RSen_M_c02_height: 156 mm; RSen_M_c02_width: 1060 mm; RSen_P_c01_description: c02_liquid piping connection; RSen_P_c01_diameter: 6.35 mm; RSen_P_c02_description: c03_gas piping connection; RSen_P_c02_diameter: 12.7 mm; RSen_P_c03_description: c04_drain piping connection; RSen_P_c03_diameter: 26 mm; TBQen_E_c01_power_factor_state: Lagging; TBQen_E_c01_system_type: Power - Balanced; TBQen_M_c01_flow_configuration: Preset; TBQen_M_c01_flow_direction: In; TBQen_M_c01_loss_method: Not Defined; TBQen_M_c01_shape: Rectangular; TBQen_M_c01_system_classification: Return Air; TBQen_M_c02_flow_configuration: Preset; TBQen_M_c02_flow_direction: Out; TBQen_M_c02_loss_method: Not Defined; TBQen_M_c02_shape: Rectangular; TBQen_M_c02_system_classification: Supply Air; TBQen_P_c01_diameter_calc: 6.4 mm; TBQen_P_c01_flow_configuration: Preset; TBQen_P_c01_flow_direction: In; TBQen_P_c01_loss_method: Not Defined; TBQen_P_c01_system_classification: Hydronic Supply; TBQen_P_c02_diameter_calc: 12.7 mm; TBQen_P_c02_flow_configuration: Preset; TBQen_P_c02_flow_direction: Out; TBQen_P_c02_loss_method: Not Defined; TBQen_P_c02_system_classification: Hydronic Return; TBQen_P_c03_diameter_calc: 26 mm; TBQen_P_c03_flow_configuration: Fixture Units; TBQen_P_c03_flow_direction: Out; TBQen_P_c03_loss_method: Not Defined; TBQen_P_c03_system_classification: Sanitary
Pset_ManufacturerTypeInformation - Manufacturer: Daikin Europe N.V.
Pset_DistributionFlowElementCommon - Reference: fna60a2veb9 - concealed floor standing unit_daikin_lxwxh 1190x200x720 mm
Constraints - Elevation: 0 mm; Level: Level: Level 1; Host: Level : Level 1
Construction - TBQen_C_alignment_index: 0; TBQen_C_GOg: no; TBQen_C_SOg: yes; TBQen_C_suspension_height: 0 mm; TBQen_C_alignment: Center
Dimensions - Area: 27.9908 m2; Volume: 3.85945 m3
Graphics - TBQen_C_clearance_zone: no; TBQen_C_connection_zone: no; TBQen_C_logo: no; TBQen_C_maintenance_zone: no; TBQen_C_neighbour_unit: no; TBQen_C_neighbour_unit_displacement_back: 0 mm; TBQen_C_neighbour_unit_displacement_front: 0 mm; TBQen_C_neighbour_unit_displacement_left: 0 mm; TBQen_C_neighbour_unit_displacement_right: 0 mm
Identity Data - Mark: 137
Mechanical - RSen_M_c01_flow_rate: 8.71095 m3/s; RSen_M_c02_flow_rate: 8.71095 m3/s; System Classification: Hydronic Return,Hydronic Supply,Sanitary,Return Air,Supply Air,Power,Controls
Mechanical - Flow - TBQen_M_flow_rate_index: 1; TBQen_M_flow_rate: 8.71095 m3/s; TBQen_M_flow_rate_info: Norm.
Other - Schedule Level: Level: Level 1; Family: RSen_55_ME_FB_indoor unit - sky air - concealed ceiling-floor_daikin: fna60a2veb9 - concealed floor standing unit_daikin_lxwxh 1190x200x720 mm; Family and Type: RSen_55_ME_FB_indoor unit - sky air - concealed ceiling-floor_daikin: fna60a2veb9 - concealed floor standing unit_daikin_lxwxh 1190x200x720 mm; Type: RSen_55_ME_FB_indoor unit - sky air - concealed ceiling-floor_daikin: fna60a2veb9 - concealed floor standing unit_daikin_lxwxh 1190x200x720 mm; Type Id: RSen_55_ME_FB_indoor unit - sky air - concealed ceiling-floor_daikin: fna60a2veb9 - concealed floor standing unit_daikin_lxwxh 1190x200x720 mm; ZZZ_V P_c01_plane_Integer: 6; ZZZ_V P_c01_X_Length: 10 mm; ZZZ_V P_c01_Y_Length: 168.5 mm
Phasing - Phase Created: New Construction
Text - RSen_C_content_manual: https://thorbiq.freshdesk.com/support/solutions

# IfcEnergyConversionDevice: fvxm50a3v1b9 - floor standing unit_daikin_lxwxh 750x238x600 mm, RSen_55_ME_FB_indoor unit - split_daikin:fvxm50a3v1b9 - floor standing unit_daikin_lxwxh 750x238x600 mm:2336249
In: Level 1
Type - PredefinedType: SPLITSYSTEM; Material: RSen_x_rgb 255 255 255 T00 pure white_gen
Type - Constraints - Default Elevation: 0 mm
Type - Construction - TBQen_C_diameter_type_index: 1; TBQen_C_SOg_ME_02: standard; TBQen_C_diameter_type: OD; TBQen_C_SOg_ME_01: RSen_55_ME_FB_SOg - fvxm50a3v1b9 - SH_daikin_tbq: standard
Type - Dimensions - RSen_C_height: 600 mm; RSen_C_length: 750 mm; RSen_C_width: 238 mm
Type - Electrical - RSen_E_c01_load_class: Other; RSen_E_c01_number_of_poles: 1; TBQen_E_c01_power_factor: 1; RSen_E_c01_division_engine: yes; RSen_E_c01_apparent_power: 30 W; RSen_E_c01_current: 0 A; RSen_E_c01_voltage: 230 V; TBQen_E_c01_power: 30 W
Type - Identity Data - Description: Floor standing; Manufacturer: Daikin Europe N.V.; Model: Split; OmniClass Number: 23.75.10.24.21.27.27; OmniClass Title: Split System Air Conditioning Units; RSen_C_code_article: FVXM50A3V1B9; RSen_C_code_ETIM: Air-conditioning split system – inside unit (evaporator); RSen_C_code_ETIM_URL: https://prod.etim-international.com/Class/Details?classId=EC011580&classVersion=4; RSen_C_code_product_class: FVXM-A9; RSen_C_content_creator: © ThorbiQ; RSen_C_content_date_changed: 14/01/2021; RSen_C_content_date_issue: 14/01/2021; RSen_C_content_provider: Daikin Europe N.V.; RSen_C_content_version: 2.0.0; RSen_C_description: Floor standing; RSen_C_model: Split; RSen_C_revit_version: 2018; RSen_C_type: Floor standing unit; RSen_C_type_comments: Indoor unit; TBQ_I BaseKeynote: 55.10.10.10; TBQen_C_code_product: FVXM50A9; TBQen_C_IFC_version: 2x3; TBQen_C_license: Creative Commons Attribution NoDerivs (CC-ND); TBQen_C_license_info: https://tldrlegal.com/license/creative-commons-attribution-noderivs-(cc-nd)#summary; Type Name: fvxm50a3v1b9 - floor standing unit_daikin_lxwxh 750x238x600 mm; URL: www.daikineurope.com
Type - Materials and Finishes - RSen_C_material: RSen_x_rgb 255 255 255 T00 pure white_gen
Type - Mechanical - RSen_P_c03_load_value: 0; RSen_P_c01_volume_flow: 0 m3/s; RSen_P_c02_volume_flow: 0 m3/s; TBQ_I Air flow rate_speed 1: 3.88461 m3/s; TBQ_I Air flow rate_speed 2: 5.2972 m3/s; TBQ_I Air flow rate_speed 3: 6.8275 m3/s
Type - Model Properties - TBQen_C_mounting_ceiling: no; TBQen_C_mounting_floor: yes; TBQen_C_mounting_wall: no
Type - Other - Category: Mechanical Equipment; TBQen_E_c01_yes_no: yes; TBQen_P_c01_yes_no: yes; TBQen_P_c02_yes_no: yes; TBQen_P_c03_yes_no: yes; TBQen_E_c02_yes_no: no; Family Name: RSen_55_ME_FB_indoor unit - split_daikin; RSen_E_c01_description: c01_el; RSen_E_c02_description: c02_controls; RSen_P_c01_description: c01_liquid piping connection; RSen_P_c01_diameter: 6.35 mm; RSen_P_c02_description: c02_gas piping connection; RSen_P_c02_diameter: 12.7 mm; RSen_P_c03_description: c03_drain piping connection; RSen_P_c03_diameter: 26 mm; TBQen_E_c01_power_factor_state: Lagging; TBQen_E_c01_system_type: Power - Balanced; TBQen_P_c01_diameter_calc: 6.4 mm; TBQen_P_c01_flow_configuration: Preset; TBQen_P_c01_flow_direction: In; TBQen_P_c01_loss_method: Not Defined; TBQen_P_c01_system_classification: Hydronic Supply; TBQen_P_c02_diameter_calc: 12.7 mm; TBQen_P_c02_flow_configuration: Preset; TBQen_P_c02_flow_direction: Out; TBQen_P_c02_loss_method: Not Defined; TBQen_P_c02_system_classification: Hydronic Return; TBQen_P_c03_diameter_calc: 26 mm; TBQen_P_c03_flow_configuration: Fixture Units; TBQen_P_c03_flow_direction: Out; TBQen_P_c03_loss_method: Not Defined; TBQen_P_c03_system_classification: Sanitary
Pset_ManufacturerTypeInformation - Manufacturer: Daikin Europe N.V.
Pset_DistributionFlowElementCommon - Reference: fvxm50a3v1b9 - floor standing unit_daikin_lxwxh 750x238x600 mm
Constraints - Elevation: 0 mm; Level: Level: Level 1; Host: Level : Level 1
Construction - TBQen_C_alignment_index: 0; TBQen_C_GOg: no; TBQen_C_SOg: yes; TBQen_C_suspension_height: 0 mm; TBQen_C_accessory_01_index: 0; TBQen_C_alignment: Center
Dimensions - Area: 16.9252 m2; Volume: 2.37718 m3
Graphics - TBQen_C_clearance_zone: no; TBQen_C_connection_zone: no; TBQen_C_logo: no; TBQen_C_maintenance_zone: no; TBQen_C_neighbour_unit: no; TBQen_C_neighbour_unit_displacement_back: 0 mm; TBQen_C_neighbour_unit_displacement_front: 0 mm; TBQen_C_neighbour_unit_displacement_left: 0 mm; TBQen_C_neighbour_unit_displacement_right: 0 mm
Identity Data - Mark: 143
Mechanical - System Classification: Hydronic Supply,Hydronic Return,Sanitary,Power,Controls
Mechanical - Flow - TBQen_M_flow_rate_index: 0; TBQen_M_flow_rate: 3.88461 m3/s; TBQen_M_flow_rate_info: Low
Other - Schedule Level: Level: Level 1; ZZZ_V P_c01_plane_Integer: 2; Family: RSen_55_ME_FB_indoor unit - split_daikin: fvxm50a3v1b9 - floor standing unit_daikin_lxwxh 750x238x600 mm; Family and Type: RSen_55_ME_FB_indoor unit - split_daikin: fvxm50a3v1b9 - floor standing unit_daikin_lxwxh 750x238x600 mm; Type: RSen_55_ME_FB_indoor unit - split_daikin: fvxm50a3v1b9 - floor standing unit_daikin_lxwxh 750x238x600 mm; Type Id: RSen_55_ME_FB_indoor unit - split_daikin: fvxm50a3v1b9 - floor standing unit_daikin_lxwxh 750x238x600 mm; ZZZ_V P_c01_X_Length: -288 mm; ZZZ_V P_c01_Y_Length: -18 mm
Phasing - Phase Created: New Construction
Text - RSen_C_content_manual: https://thorbiq.freshdesk.com/support/solutions

# IfcEnergyConversionDevice: hxhd125a8v1b - high temperature hydrobox for vrv_daikin_lxwxh 600x694x708 mm, RSen_53_ME_FB_hydrobox_daikin:hxhd125a8v1b - high temperature hydrobox for vrv_daikin_lxwxh 600x694x708 mm:1431636
In: Level 1
Type - PredefinedType: WATER; Classification: 53.30.10.2 (Uniformat); Material: RSen_x_rgb 255 255 255 T00 pure white_gen
Type - Constraints - Default Elevation: 0 mm; WT_H Suspension: no; WT_H Angled wall mounted: no; WT_H Bounding Box: standard; WT_H Ceiling mounted: no; WT_H Cut out_diameter: 344 mm; WT_H Cut out_height: 0 mm; WT_H Cut out_height negative: 2 mm; WT_H Cut out_length: 0 mm; WT_H Cut out_length_: 1 mm; WT_H Cut out_radius: 1 mm; WT_H Cut out_width: 0 mm; WT_H Cut out_width_: 1 mm; WT_H Half length negative: -300 mm; WT_H Half width negative: -347 mm; WT_H Hash: 54952dfbbe01a22e14fb2962b80523c9; WT_H Height: 708 mm; WT_H Height_Width: 708 mm; WT_H Height negative: -708 mm; WT_H Length: 600 mm; WT_H Logo_plane: 1; WT_H Logo_Rotation about axis: 0 deg; WT_H Logo_X: 0 mm; WT_H Logo_Y: 0 mm; WT_H Logo_Z: 0 mm; WT_H Lookup table name: RSen_55_ME_FB_indoor unit - outdoor unit; WT_H Parallel wall mounted: no; WT_H Pendant - horizontal mounted: no; WT_H Pendant - vertical mounted: no; WT_H Recess depth: 0 mm; WT_H Recess depth_negative: 0 mm; WT_H Recessed: no; WT_H Surface mounted: yes; WT_H Suspension_type: none_gen; WT_H Visualized connectors: standard; WT_H Width: 694 mm; WT_H Width_Height: 694 mm; WT_H Zones_plane: 2
Type - Construction - RSen_C_diameter_type: OD; RSen_C_diameter_type_index: 1; TBQen_C_SOg_01: RSen_53_ME_FB_SOg - hxhd125a8v1b - SH_daikin_tbq: standard; TBQen_C_SOg_02: standard; WT_V Component_01_description: -; WT_V Component_01_height: 708 mm; WT_V Component_01_length: 600 mm; WT_V Component_01_plane: 2; WT_V Component_01_width: 694 mm; WT_V Component_01_X: 0 mm; WT_V Component_01_Y: 0 mm; WT_V Component_01_Z: 0 mm; WT_V Component_02_description: -; WT_V Component_02_height: 0 mm; WT_V Component_02_length: 0 mm; WT_V Component_02_plane: 2; WT_V Component_02_width: 0 mm; WT_V Component_02_X: 0 mm; WT_V Component_02_Y: 0 mm; WT_V Component_02_Z: 0 mm; WT_V Component_03_description: -; WT_V Component_03_height: 0 mm; WT_V Component_03_length: 0 mm; WT_V Component_03_plane: 1; WT_V Component_03_width: 0 mm; WT_V Component_03_X: 0 mm; WT_V Component_03_Y: 0 mm; WT_V Component_03_Z: 0 mm; WT_V Logo: RSen_55_GM_FB_logo - SH_daikin: standard; WT_V SOg_plane: 2; WT_V SOg_rotation: 0 deg; WT_V SOg_X: 0 mm; WT_V SOg_Y: 0 mm; WT_V SOg_Z: 0 mm; WT_V Suspension_length: 0 mm; WT_V Suspension_offset: 0 mm; WT_V Suspension_width: 0 mm; WT_V Suspension_X: 0 mm; WT_V Suspension_Y: 0 mm
Type - Dimensions - RSen_C_height: 708 mm; RSen_C_length: 600 mm; RSen_C_width: 694 mm
Type - Electrical - RSen_E_c01_division_engine: no; RSen_E_c01_load_class: Other; RSen_E_c01_number_of_poles: 1; RSen_E_c01_apparent_power: 5 W; RSen_E_c01_current: 0 A; RSen_E_c01_power: 5 W; RSen_E_c01_power_factor: 1; RSen_E_c01_voltage: 230 V
Type - Graphics - WT_V Clearance zone_back: 0 mm; WT_V Clearance zone_bottom: 0 mm; WT_V Clearance zone_front: 600 mm; WT_V Clearance zone_left: 250 mm; WT_V Clearance zone_right: 250 mm; WT_V Clearance zone_top: 0 mm; WT_V Connection zone_back: 0 mm; WT_V Connection zone_bottom: 0 mm; WT_V Connection zone_front: 0 mm; WT_V Connection zone_left: 0 mm; WT_V Connection zone_right: 0 mm; WT_V Connection zone_top: 0 mm; WT_V Grid_height: 600 mm; WT_V Grid_width: 600 mm; WT_V Maintenance zone_back: 0 mm; WT_V Maintenance zone_bottom: 0 mm; WT_V Maintenance zone_front: 0 mm; WT_V Maintenance zone_left: 0 mm; WT_V Maintenance zone_right: 0 mm; WT_V Maintenance zone_top: 0 mm; WT_V Neighbour unit_offset_back: 0 mm; WT_V Neighbour unit_offset_front: 0 mm; WT_V Neighbour unit_offset_left: 0 mm; WT_V Neighbour unit_offset_right: 0 mm; WT_V Symbol_ceiling: none_gen; WT_V Symbol_wall: none_gen
Type - Identity Data - Assembly Code: 53.30.10.2; Description: Heating Only; Manufacturer: Daikin Europe N.V.; Model: Altherma; OmniClass Number: 23.75.70.17; OmniClass Title: Water Heated and Cooled Terminal Heating and Cooling Units; RSen_C_code_article: HXHD125A8V1B; RSen_C_code_ETIM: Boiler indirectly heated; RSen_C_code_ETIM_URL: https://prod.etim-international.com/Class/Details?classId=EC011392&classVersion=5; RSen_C_code_gtin: -; RSen_C_code_product: HXHD125A8; RSen_C_code_product_class: HXHD-A8; RSen_C_content_creator: © ThorbiQ; RSen_C_content_date_changed: 14/10/2019; RSen_C_content_date_issue: 14/10/2019; RSen_C_content_provider: Daikin Europe N.V.; RSen_C_content_version: 1.1.3; RSen_C_description: Heating Only; RSen_C_IFC_version: 2x3; RSen_C_license: Creative Commons Attribution NoDerivs (CC-ND); RSen_C_license_info: https://tldrlegal.com/license/creative-commons-attribution-noderivs-(cc-nd)#summary; RSen_C_model: Altherma; RSen_C_revit_version: 2016; RSen_C_type: High temperature hydrobox for VRV; RSen_C_type_comments: Indoor Unit; TBQ_I BaseKeynote: 53.30.10.2 53.30.10.2; Type Comments: Indoor Unit; Type Name: hxhd125a8v1b - high temperature hydrobox for vrv_daikin_lxwxh 600x694x708 mm; URL: www.daikineurope.com
Type - Materials and Finishes - RSen_C_material: RSen_x_rgb 255 255 255 T00 pure white_gen; WT_V Clearance zone_material: RSen_x_rgb 255 128 128 T80 red_gen; WT_V Component_01_material: RSen_x_rgb 255 255 255 T00 pure white_gen; WT_V Component_02_material: RSen_x_rgb 255 255 255 T00 pure white_gen; WT_V Component_03_material: RSen_x_rgb 255 255 255 T00 pure white_gen; WT_V Connection zone_material: RSen_x_rgb 255 128 128 T80 red_gen; WT_V Maintenance zone_material: RSen_x_rgb 255 128 128 T80 red_gen; WT_V Placement zone_material: RSen_x_rgb 255 128 128 T80 red_gen
Type - Model Properties - Casing Colour: Metallic grey; Casing Material: Precoated sheet metal; Cooling capacity Nom. kW: -; Current Recommended fuses A: 20 A; Dimensions Unit HeightxWidthxDepth mm: 705x600x695 mm; Heating capacity Nom. kW: 14.0 (1) kW; Installation Manual: http://www.daikineurope.com/support-and-manuals/product-information/index.jsp?searchterm=HXHD-A8&searchcategory=product-information; Operation range Domestic hot water Ambient Min./Max. °CDB: -20/43 °CDB; Operation range Domestic hot water Water side Min./Max. °C: 45/75 °C; Operation range Heating Ambient Min./Max. °C: -20/20 / 24 (7) °C; Operation range Heating Water side Min./Max. °C: 25/80 °C; Power supply Phase/Frequency/Voltage: 1~/50 Hz/220-240 V; Refrigerant Charge kg: 2 kg; Refrigerant Charge TCO2Eq: 2.9 TCO2Eq; Refrigerant circuit Gas side diameter mm: 12.7 mm; Refrigerant circuit Liquid side diameter mm: 9.52 mm; Refrigerant GWP: 1,430.0; Refrigerant Type: R-134a; Sound power level Nom. dBA: 55 (3) dBA; Sound pressure level Night quiet mode Level 1 dBA: 38 (3) dBA; Sound pressure level Nom. dBA: 42 (3) / 43 (6) dBA; Specification Text: https://my.daikin.eu/denv/en_US/home/applications/asset-finder.html##%3Fi=1%3Bq4=document-language%253Aen%7Cdocument-language%253Anone%3Bq5=document-type%253Aspecification-text%3Bsort=date%3Bsp_d=specific%3Bsp_start_day=1%3Bsp_start_month=1%3Bsp_start_year=2011%3Btemplate=json%3Bx3=market%3Bx4=document-language%3Bx5=document-type%3Bq=HXHD-A8%3B; Water circuit Heating water system Water volume Max./Min. L: 200/20 l; Water circuit Piping connections diameter inch: G 1" (female) inch; Weight Unit kg: 92 kg
Type - Other - Category: Mechanical Equipment; Family Name: RSen_53_ME_FB_hydrobox_daikin; RSen_E_c01_description: c01_el; RSen_E_c01_power_factor_state: Lagging; RSen_E_c01_system_type: Power - Balanced; RSen_E_c01_yes_no: yes; RSen_E_c02_description: c02_controls; RSen_E_c02_yes_no: yes; RSen_P_c01_description: c01_water out connection; RSen_P_c01_diameter: 25 mm; RSen_P_c01_diameter_calc: 25 mm; RSen_P_c01_flow_configuration: Calculated; RSen_P_c01_flow_direction: Out; RSen_P_c01_loss_method: Not Defined; RSen_P_c01_system_classification: Hydronic Supply; RSen_P_c01_yes_no: yes; RSen_P_c02_description: c02_water in connection; RSen_P_c02_diameter: 25 mm; RSen_P_c02_diameter_calc: 25 mm; RSen_P_c02_flow_configuration: Calculated; RSen_P_c02_flow_direction: In; RSen_P_c02_loss_method: Not Defined; RSen_P_c02_system_classification: Hydronic Return; RSen_P_c02_yes_no: yes; RSen_P_c03_description: c03_liquid pipe connection; RSen_P_c03_diameter: 9.52 mm; RSen_P_c03_diameter_calc: 9.5 mm; RSen_P_c03_flow_configuration: Preset; RSen_P_c03_flow_direction: In; RSen_P_c03_loss_method: Not Defined; RSen_P_c03_system_classification: Hydronic Supply; RSen_P_c03_yes_no: yes; RSen_P_c04_description: c04_discharge gas connection; RSen_P_c04_diameter: 12.7 mm; RSen_P_c04_diameter_calc: 12.7 mm; RSen_P_c04_flow_configuration: Preset; RSen_P_c04_flow_direction: Out; RSen_P_c04_loss_method: Not Defined; RSen_P_c04_system_classification: Hydronic Return; RSen_P_c04_yes_no: yes; WT_V E_c01_plane: 2; WT_V E_c01_X: 0 mm; WT_V E_c01_Y: 0 mm; WT_V E_c01_Z: 0 mm; WT_V P_c01_length: 60 mm; WT_V P_c01_plane: 4; WT_V P_c01_X: -165 mm; WT_V P_c01_Y: -4 mm; WT_V P_c01_Z: -81 mm; WT_V P_c02_length: 60 mm; WT_V P_c02_plane: 4; WT_V P_c02_X: -200 mm; WT_V P_c02_Y: 206 mm; WT_V P_c02_Z: -81 mm; WT_V P_c03_length: 60 mm; WT_V P_c03_plane: 4; WT_V P_c03_X: 65 mm; WT_V P_c03_Y: 284 mm; WT_V P_c03_Z: -81 mm; WT_V P_c04_length: 60 mm; WT_V P_c04_plane: 4; WT_V P_c04_X: 144 mm; WT_V P_c04_Y: 269 mm; WT_V P_c04_Z: -81 mm
Pset_ManufacturerTypeInformation - Manufacturer: Daikin Europe N.V.
Pset_DistributionFlowElementCommon - Reference: hxhd125a8v1b - high temperature hydrobox for vrv_daikin_lxwxh 600x694x708 mm
Constraints - Elevation: 0 mm; Level: Level: Level 1; WT_H Suspension_height: 0 mm; Host: Level : Level 1; WT_H Half width: 347 mm; WT_H Logo LOD200: no; WT_H Logo LOD400: no; WT_H Offset from base level: 0 mm; WT_H Suspension_height x 2: 0 mm; WT_H X: 300 mm; WT_H Y: 347 mm
Construction - TBQen_C_GOg: no; TBQen_C_SOg: yes; RSen_C_alignment: Center; RSen_C_alignment_index: 0; RSen_C_offset_from_base_level: 0 mm; RSen_C_suspension_height: 0 mm
Dimensions - Area: 25.7857 m2; Volume: 6.01963 m3
Graphics - TBQen_C_logo: no; RSen_C_clearance_zone: no; RSen_C_connection_zone: no; RSen_C_maintenance_zone: no; RSen_C_neighbour_unit: no; RSen_C_neighbour_unit_displacement_back: 0 mm; RSen_C_neighbour_unit_displacement_front: 0 mm; RSen_C_neighbour_unit_displacement_left: 0 mm; RSen_C_neighbour_unit_displacement_right: 0 mm
Identity Data - Mark: 92
Mechanical - RSen_P_c01_volume_flow: 0 m3/s; RSen_P_c02_volume_flow: 0 m3/s; RSen_P_c03_volume_flow: 0 m3/s; RSen_P_c04_volume_flow: 0 m3/s; System Classification: Hydronic Return,Hydronic Supply,Power,Hydronic Return,Controls
Other - Schedule Level: Level: Level 1; Family: RSen_53_ME_FB_hydrobox_daikin: hxhd125a8v1b - high temperature hydrobox for vrv_daikin_lxwxh 600x694x708 mm; Family and Type: RSen_53_ME_FB_hydrobox_daikin: hxhd125a8v1b - high temperature hydrobox for vrv_daikin_lxwxh 600x694x708 mm; Type: RSen_53_ME_FB_hydrobox_daikin: hxhd125a8v1b - high temperature hydrobox for vrv_daikin_lxwxh 600x694x708 mm; Type Id: RSen_53_ME_FB_hydrobox_daikin: hxhd125a8v1b - high temperature hydrobox for vrv_daikin_lxwxh 600x694x708 mm
Phasing - Phase Created: New Construction
Text - RSen_C_content_manual: https://thorbiq.freshdesk.com/support/solutions

# IfcEnergyConversionDevice: uatyq20abay1 - rooftop_daikin_lxwxh 1790x1730x1600 mm, RSen_57_ME_FB_rooftop unit_daikin:uatyq20abay1 - rooftop_daikin_lxwxh 1790x1730x1600 mm:1703046
In: Level 1
Type - PredefinedType: ROOFTOPUNIT; Material: RSen_x_rgb 255 255 255 T00 pure white_gen
Type - Constraints - Default Elevation: 0 mm
Type - Construction - TBQen_C_diameter_type_index: 1; TBQen_C_SOg_ME_02: standard; TBQen_C_suspension_height: 0 mm; TBQen_C_accessory_01_index: 0; TBQen_C_diameter_type: OD; TBQen_C_SOg_ME_01: RSen_57_ME_FB_SOg - uatyq20abay1 - SH_daikin_tbq: standard
Type - Dimensions - RSen_C_height: 1600 mm; RSen_C_length: 1790 mm; RSen_C_width: 1730 mm
Type - Electrical - RSen_E_c01_load_class: Other; TBQen_E_c01_power_factor: 1; RSen_E_c01_division_engine: yes; RSen_E_c01_number_of_poles: 3; RSen_E_c01_apparent_power: 6600 W; RSen_E_c01_current: 0 A; RSen_E_c01_voltage: 400 V; TBQen_E_c01_power: 6600 W
Type - Identity Data - Description: Heat Pump; Manufacturer: Daikin Europe N.V.; Model: Rooftop; OmniClass Number: 23.75.35.14.21; OmniClass Title: Modular Rooftop Air Handling Units; RSen_C_code_article: UATYQ20ABAY1; RSen_C_code_ETIM: Air-conditioning split system – inside unit (evaporator); RSen_C_code_ETIM_URL: https://prod.etim-international.com/Class/Details?classId=EC011580&classVersion=4; RSen_C_code_product_class: UATYQ-ABAY1; RSen_C_content_creator: © ThorbiQ; RSen_C_content_date_changed: 14/01/2021; RSen_C_content_date_issue: 14/01/2021; RSen_C_content_provider: Daikin Europe N.V.; RSen_C_content_version: 2.0.0; RSen_C_description: Heat Pump; RSen_C_model: Rooftop; RSen_C_revit_version: 2018; RSen_C_type: Rooftop; RSen_C_type_comments: Single Unit; TBQ_I BaseKeynote: 55.10.10.10; TBQen_C_code_product: UATYQ20ABAY1; TBQen_C_IFC_version: 2x3; TBQen_C_license: Creative Commons Attribution NoDerivs (CC-ND); TBQen_C_license_info: https://tldrlegal.com/license/creative-commons-attribution-noderivs-(cc-nd)#summary; Type Name: uatyq20abay1 - rooftop_daikin_lxwxh 1790x1730x1600 mm; URL: www.daikineurope.com
Type - Materials and Finishes - RSen_C_material: RSen_x_rgb 255 255 255 T00 pure white_gen
Type - Mechanical - RSen_P_c01_load_value: 0; TBQ_I Air flow rate_speed 1: 0 m3/s; TBQ_I Air flow rate_speed 2: 48.5577 m3/s; TBQ_I Air flow rate_speed 3: 0 m3/s
Type - Model Properties - TBQen_C_mounting_ceiling: no; TBQen_C_mounting_floor: yes; TBQen_C_mounting_wall: no
Type - Other - Category: Mechanical Equipment; TBQen_E_c01_yes_no: yes; TBQen_P_c01_yes_no: yes; Family Name: RSen_57_ME_FB_rooftop unit_daikin; RSen_E_c01_description: c01_el; RSen_E_c02_description: c02_controls; RSen_M_c01_description: c01_return air; RSen_M_c01_diameter: 0 mm; RSen_M_c02_description: c02_supply air; RSen_M_c02_diameter: 0 mm; RSen_P_c01_description: c01_drain piping connection; RSen_P_c01_diameter: 25 mm; TBQen_E_c01_power_factor_state: Lagging; TBQen_E_c01_system_type: Power - Balanced; TBQen_E_c02_yes_no: no; TBQen_M_c01_flow_configuration: Calculated; TBQen_M_c01_flow_direction: in; TBQen_M_c01_loss_method: Not Defined; TBQen_M_c01_optional: no; TBQen_M_c01_shape: Rectangular; TBQen_M_c01_system_classification: Return Air; TBQen_M_c01_yes_no: yes; TBQen_M_c02_flow_configuration: Calculated; TBQen_M_c02_flow_direction: Out; TBQen_M_c02_loss_method: Not Defined; TBQen_M_c02_optional: no; TBQen_M_c02_shape: Rectangular; TBQen_M_c02_system_classification: Supply Air; TBQen_M_c02_yes_no: yes; TBQen_P_c01_diameter_calc: 25 mm; TBQen_P_c01_flow_configuration: Fixture Units; TBQen_P_c01_flow_direction: Out; TBQen_P_c01_loss_method: Not Defined; TBQen_P_c01_system_classification: Sanitary
Pset_ManufacturerTypeInformation - Manufacturer: Daikin Europe N.V.
Pset_DistributionFlowElementCommon - Reference: uatyq20abay1 - rooftop_daikin_lxwxh 1790x1730x1600 mm
Constraints - Elevation: 0 mm; Level: Level: Level 1; Host: Level : Level 1
Construction - TBQen_C_alignment_index: 0; TBQen_C_GOg: no; TBQen_C_SOg: yes; TBQen_C_alignment: Center; TBQen_C_connection_drain_position: Front drain; TBQen_C_connection_drain_position_index: 0; TBQen_C_connection_return_position: Rear intake; TBQen_C_connection_return_position_index: 2; TBQen_C_connection_supply_position: Left discharge; TBQen_C_connection_supply_position_index: 1
Dimensions - Area: 222.516 m2; Volume: 139.581 m3
Graphics - TBQen_C_clearance_zone: no; TBQen_C_connection_zone: no; TBQen_C_logo: no; TBQen_C_maintenance_zone: no; TBQen_C_neighbour_unit: no; TBQen_C_neighbour_unit_displacement_back: 0 mm; TBQen_C_neighbour_unit_displacement_front: 0 mm; TBQen_C_neighbour_unit_displacement_left: 0 mm; TBQen_C_neighbour_unit_displacement_right: 0 mm
Identity Data - Mark: 109
Mechanical - RSen_M_c01_flow_rate: 0 m3/s; RSen_M_c02_flow_rate: 0 m3/s; System Classification: Supply Air,Power,Controls,Return Air,Sanitary
Mechanical - Flow - TBQen_M_flow_rate: 0 m3/s; TBQen_M_flow_rate_index: 0; TBQen_M_flow_rate_info: Low
Other - Schedule Level: Level: Level 1; Family: RSen_57_ME_FB_rooftop unit_daikin: uatyq20abay1 - rooftop_daikin_lxwxh 1790x1730x1600 mm; Family and Type: RSen_57_ME_FB_rooftop unit_daikin: uatyq20abay1 - rooftop_daikin_lxwxh 1790x1730x1600 mm; RSen_M_c01_height: 1145 mm; RSen_M_c01_width: 250 mm; RSen_M_c02_height: 1140 mm; RSen_M_c02_width: 318 mm; Type: RSen_57_ME_FB_rooftop unit_daikin: uatyq20abay1 - rooftop_daikin_lxwxh 1790x1730x1600 mm; Type Id: RSen_57_ME_FB_rooftop unit_daikin: uatyq20abay1 - rooftop_daikin_lxwxh 1790x1730x1600 mm
Phasing - Phase Created: New Construction
Text - RSen_C_content_manual: https://thorbiq.freshdesk.com/support/solutions

# IfcFlowStorageDevice: ekhtsu260ac - domestic hot water tank_daikin_lxwxh 600x695x1610 mm, RSen_53_ME_FB_domestic hot water tank_daikin:ekhtsu260ac - domestic hot water tank_daikin_lxwxh 600x695x1610 mm:1431417
In: Level 1
Type - Classification: 53.30.10.30 (Uniformat); Material: RSen_x_rgb 255 255 255 T00 pure white_gen
Type - Constraints - Default Elevation: 0 mm; TBQ_H Accessory: standard; TBQ_H Accessory_info: NA; TBQ_H Accessory_none: standard; TBQ_H Accessory_plane: 2; TBQ_H Accessory position_X: 0 mm; TBQ_H Accessory position_Y: 0 mm; TBQ_H Angled wall mounted: no; TBQ_H Bounding Box: standard; TBQ_H Ceiling mounted: no; TBQ_H Cut out_diameter: 0 mm; TBQ_H Cut out_height: 0 mm; TBQ_H Cut out_height negative: -2 mm; TBQ_H Cut out_length: 0 mm; TBQ_H Cut out_length_: 1 mm; TBQ_H Cut out_radius: 1 mm; TBQ_H Cut out_width: 0 mm; TBQ_H Cut out_width_: 1 mm; TBQ_H Cut out_X: 0 mm; TBQ_H Cut out_Y: 0 mm; TBQ_H Diameter: 0 mm; TBQ_H Hash: cb0e81e96aa9cb63e5e8fa91622fa6b0; TBQ_H Height: 1610 mm; TBQ_H Height negative: -1610 mm; TBQ_H Length: 600 mm; TBQ_H Logo_plane: 1; TBQ_H Logo_Rotation about axis: 0 deg; TBQ_H Logo_X: 0 mm; TBQ_H Logo_Y: 0 mm; TBQ_H Logo_Z: 0 mm; TBQ_H Lookup table name: RSen_55_ME_FB_indoor unit - outdoor unit; TBQ_H Parallel wall mounted: no; TBQ_H Pendant - horizontal mounted: no; TBQ_H Pendant - vertical mounted: no; TBQ_H Recess depth: 0 mm; TBQ_H Recess depth_negative: 0 mm; TBQ_H Recessed: no; TBQ_H Surface mounted: yes; TBQ_H Suspension: no; TBQ_H Suspension_type: none_gen; TBQ_H Visualized connectors: standard; TBQ_H Width: 695 mm; TBQ_H Width_Height: 695 mm; TBQ_H Zones_plane: 2
Type - Construction - TBQen_C_diameter_type_index: 1; TBQen_C_SOg_ME_02: standard; TBQ_V Component_01_description: -; TBQ_V Component_01_diameter: 0 mm; TBQ_V Component_01_height: 1610 mm; TBQ_V Component_01_length: 600 mm; TBQ_V Component_01_plane: 2; TBQ_V Component_01_width: 695 mm; TBQ_V Component_01_X: 0 mm; TBQ_V Component_01_Y: 0 mm; TBQ_V Component_01_Z: 0 mm; TBQ_V Component_02_description: -; TBQ_V Component_02_diameter: 0 mm; TBQ_V Component_02_height: 0 mm; TBQ_V Component_02_length: 0 mm; TBQ_V Component_02_plane: 2; TBQ_V Component_02_width: 0 mm; TBQ_V Component_02_X: 0 mm; TBQ_V Component_02_Y: 0 mm; TBQ_V Component_02_Z: 0 mm; TBQ_V Component_03_description: -; TBQ_V Component_03_diameter: 0 mm; TBQ_V Component_03_height: 0 mm; TBQ_V Component_03_length: 0 mm; TBQ_V Component_03_plane: 1; TBQ_V Component_03_width: 0 mm; TBQ_V Component_03_X: 0 mm; TBQ_V Component_03_Y: 0 mm; TBQ_V Component_03_Z: 0 mm; TBQ_V SOg_plane: 2; TBQ_V SOg_rotation: 90 deg; TBQ_V SOg_X: 0 mm; TBQ_V SOg_Y: 0 mm; TBQ_V SOg_Z: 0 mm; TBQ_V Suspension_length: 0 mm; TBQ_V Suspension_offset: 0 mm; TBQ_V Suspension_width: 0 mm; TBQen_C_accessory_01_index: 0; TBQen_C_diameter_type: OD; TBQen_C_SOg_ME_01: RSen_53_ME_FB_SOg - ekhtsu260ac - SH_daikin_tbq: standard
Type - Dimensions - RSen_C_diameter: 0 mm; RSen_C_height: 1610 mm; RSen_C_length: 600 mm; RSen_C_width: 695 mm
Type - Electrical - RSen_E_c01_load_class: Other; RSen_E_c01_number_of_poles: 1; TBQen_E_c01_power_factor: 1; RSen_E_c01_apparent_power: 0 W; RSen_E_c01_current: 0 A; RSen_E_c01_division_engine: yes; RSen_E_c01_voltage: 230 V; TBQen_E_c01_power: 0 W
Type - Graphics - TBQ_V Clearance zone_angle end: 0 deg; TBQ_V Clearance zone_angle start: 0 deg; TBQ_V Clearance zone_back: 0 mm; TBQ_V Clearance zone_bottom: 0 mm; TBQ_V Clearance zone_front: 600 mm; TBQ_V Clearance zone_left: 250 mm; TBQ_V Clearance zone_offset range: 0 mm; TBQ_V Clearance zone_right: 250 mm; TBQ_V Clearance zone_top: 30 mm; TBQ_V Connection zone_angle end: 0 deg; TBQ_V Connection zone_angle start: 0 deg; TBQ_V Connection zone_back: 0 mm; TBQ_V Connection zone_bottom: 0 mm; TBQ_V Connection zone_front: 0 mm; TBQ_V Connection zone_left: 0 mm; TBQ_V Connection zone_offset range: 0 mm; TBQ_V Connection zone_right: 0 mm; TBQ_V Connection zone_top: 0 mm; TBQ_V Grid_height: 600 mm; TBQ_V Grid_width: 600 mm; TBQ_V Logo: RSen_55_GM_FB_logo - SH_daikin: standard; TBQ_V Maintenance zone_angle end: 0 deg; TBQ_V Maintenance zone_angle start: 0 deg; TBQ_V Maintenance zone_back: 0 mm; TBQ_V Maintenance zone_bottom: 0 mm; TBQ_V Maintenance zone_front: 0 mm; TBQ_V Maintenance zone_left: 0 mm; TBQ_V Maintenance zone_offset range: 0 mm; TBQ_V Maintenance zone_right: 0 mm; TBQ_V Maintenance zone_top: 0 mm; TBQ_V Neighbour unit_offset_back: 0 mm; TBQ_V Neighbour unit_offset_front: 0 mm; TBQ_V Neighbour unit_offset_left: 0 mm; TBQ_V Neighbour unit_offset_right: 0 mm; TBQ_V Symbol_ceiling: none_gen; TBQ_V Symbol_wall: none_gen
Type - Identity Data - Assembly Code: 53.30.10.30; Description: Heating; Manufacturer: Daikin Europe N.V.; Model: Altherma Domestic Hot Water Tank; OmniClass Number: 23.65.35.11.11; OmniClass Title: Storage Water Heaters; RSen_C_code_article: EKHTSU260AC; RSen_C_code_ETIM: Storage water heater for solar system; RSen_C_code_ETIM_URL: https://prod.etim-international.com/Class/Details?classId=EC011580&classVersion=4; RSen_C_code_product_class: EKHTSU-AC; RSen_C_content_creator: © ThorbiQ; RSen_C_content_date_changed: 11/11/2021; RSen_C_content_date_issue: 11/11/2021; RSen_C_content_provider: Daikin Europe N.V.; RSen_C_content_version: 2.0.0; RSen_C_description: Heating; RSen_C_model: Altherma Domestic Hot Water Tank; RSen_C_revit_version: 2019; RSen_C_type: Domestic hot water tank; RSen_C_type_comments: Accessory; TBQ_I BaseKeynote: 53.30.10.30; TBQen_C_code_product: EKHTSU260AC; TBQen_C_IFC_version: 2x3; TBQen_C_license: Creative Commons Attribution NoDerivs (CC-ND); TBQen_C_license_info: https://tldrlegal.com/license/creative-commons-attribution-noderivs-(cc-nd)#summary; Type Comments: Accessory; Type Name: ekhtsu260ac - domestic hot water tank_daikin_lxwxh 600x695x1610 mm; URL: www.daikineurope.com
Type - Materials and Finishes - RSen_C_material: RSen_x_rgb 255 255 255 T00 pure white_gen; TBQ_V Clearance zone_material: RSen_x_rgb 255 128 128 T80 red_gen; TBQ_V Component_01_material: RSen_x_rgb 255 255 255 T00 pure white_gen; TBQ_V Component_02_material: RSen_x_rgb 255 255 255 T00 pure white_gen; TBQ_V Component_03_material: RSen_x_rgb 255 255 255 T00 pure white_gen; TBQ_V Connection zone_material: RSen_x_rgb 255 128 128 T80 red_gen; TBQ_V Maintenance zone_material: RSen_x_rgb 255 128 128 T80 red_gen; TBQ_V Placement zone_material: RSen_x_rgb 255 128 128 T80 red_gen
Type - Model Properties - TBQen_C_mounting_ceiling: no; TBQen_C_mounting_floor: yes; TBQen_C_mounting_wall: no
Type - Other - Category: Mechanical Equipment; TBQen_E_c01_yes_no: yes; TBQen_E_c02_yes_no: yes; TBQen_P_c01_yes_no: yes; TBQen_P_c02_yes_no: yes; TBQen_P_c03_yes_no: yes; TBQen_P_c04_yes_no: yes; TBQen_P_c05_yes_no: yes; Family Name: RSen_53_ME_FB_domestic hot water tank_daikin; RSen_E_c01_description: c01_el; RSen_E_c02_description: c02_controls; RSen_P_c01_description: c01_hot water out; RSen_P_c01_diameter: 20 mm; RSen_P_c02_description: c02_cold water in; RSen_P_c02_diameter: 20 mm; RSen_P_c03_description: c03_water inlet heat exchanger; RSen_P_c03_diameter: 20 mm; RSen_P_c04_description: c04_water outlet heat exchanger; RSen_P_c04_diameter: 20 mm; RSen_P_c05_description: c05_recirculation connection; RSen_P_c05_diameter: 15 mm; RSen_P_c06_description: -; RSen_P_c06_diameter: 0 mm; RSen_P_c07_description: -; RSen_P_c07_diameter: 0 mm; RSen_P_c08_description: -; RSen_P_c08_diameter: 0 mm; TBQ_V E_c01_plane: 2; TBQ_V E_c01_X: 0 mm; TBQ_V E_c01_Y: 0 mm; TBQ_V E_c01_Z: 0 mm; TBQ_V P_c01_angle: 0 deg; TBQ_V P_c01_length: 100 mm; TBQ_V P_c01_plane: 2; TBQ_V P_c01_X: 150 mm; TBQ_V P_c01_Y: -50 mm; TBQ_V P_c01_Z: -103 mm; TBQ_V P_c02_angle: 0 deg; TBQ_V P_c02_length: 100 mm; TBQ_V P_c02_plane: 2; TBQ_V P_c02_X: -150 mm; TBQ_V P_c02_Y: -50 mm; TBQ_V P_c02_Z: -103 mm; TBQ_V P_c03_angle: 0 deg; TBQ_V P_c03_length: 100 mm; TBQ_V P_c03_plane: 2; TBQ_V P_c03_X: 150 mm; TBQ_V P_c03_Y: 59 mm; TBQ_V P_c03_Z: -103 mm; TBQ_V P_c04_angle: 0 deg; TBQ_V P_c04_length: 100 mm; TBQ_V P_c04_plane: 2; TBQ_V P_c04_X: -150 mm; TBQ_V P_c04_Y: 59 mm; TBQ_V P_c04_Z: -103 mm; TBQ_V P_c05_angle: 0 deg; TBQ_V P_c05_length: 100 mm; TBQ_V P_c05_plane: 2; TBQ_V P_c05_X: 0 mm; TBQ_V P_c05_Y: -95 mm; TBQ_V P_c05_Z: -103 mm; TBQ_V P_c06_angle: 0 deg; TBQ_V P_c06_length: 0 mm; TBQ_V P_c06_plane: 0; TBQ_V P_c06_X: 0 mm; TBQ_V P_c06_Y: 0 mm; TBQ_V P_c06_Z: 0 mm; TBQ_V P_c07_angle: 0 deg; TBQ_V P_c07_length: 0 mm; TBQ_V P_c07_plane: 0; TBQ_V P_c07_X: 0 mm; TBQ_V P_c07_Y: 0 mm; TBQ_V P_c07_Z: 0 mm; TBQ_V P_c08_angle: 0 deg; TBQ_V P_c08_length: 0 mm; TBQ_V P_c08_plane: 0; TBQ_V P_c08_X: 0 mm; TBQ_V P_c08_Y: 0 mm; TBQ_V P_c08_Z: 0 mm; TBQen_E_c01_power_factor_state: Lagging; TBQen_E_c01_system_type: Power - Balanced; TBQen_P_c01_diameter_calc: 20 mm; TBQen_P_c01_flow_configuration: Calculated; TBQen_P_c01_flow_direction: Out; TBQen_P_c01_loss_method: Not Defined; TBQen_P_c01_system_classification: Domestic Hot Water; TBQen_P_c02_diameter_calc: 20 mm; TBQen_P_c02_flow_configuration: Preset; TBQen_P_c02_flow_direction: In; TBQen_P_c02_loss_method: Not Defined; TBQen_P_c02_system_classification: Domestic Cold Water; TBQen_P_c03_diameter_calc: 20 mm; TBQen_P_c03_flow_configuration: Preset; TBQen_P_c03_flow_direction: In; TBQen_P_c03_loss_method: Not Defined; TBQen_P_c03_system_classification: Hydronic Supply; TBQen_P_c04_diameter_calc: 20 mm; TBQen_P_c04_flow_configuration: Preset; TBQen_P_c04_flow_direction: Out; TBQen_P_c04_loss_method: Not Defined; TBQen_P_c04_system_classification: Hydronic Return; TBQen_P_c05_diameter_calc: 15 mm; TBQen_P_c05_flow_configuration: Calculated; TBQen_P_c05_flow_direction: In; TBQen_P_c05_loss_method: Not Defined; TBQen_P_c05_system_classification: Domestic Hot Water; TBQen_P_c06_diameter_calc: 0 mm; TBQen_P_c06_flow_configuration: -; TBQen_P_c06_flow_direction: -; TBQen_P_c06_loss_method: -; TBQen_P_c06_system_classification: -; TBQen_P_c06_yes_no: no; TBQen_P_c07_diameter_calc: 0 mm; TBQen_P_c07_flow_configuration: -; TBQen_P_c07_flow_direction: -; TBQen_P_c07_loss_method: -; TBQen_P_c07_system_classification: -; TBQen_P_c07_yes_no: no; TBQen_P_c08_diameter_calc: 0 mm; TBQen_P_c08_flow_configuration: -; TBQen_P_c08_flow_direction: -; TBQen_P_c08_loss_method: -; TBQen_P_c08_system_classification: -; TBQen_P_c08_yes_no: no
Pset_ManufacturerTypeInformation - Manufacturer: Daikin Europe N.V.
Pset_DistributionFlowElementCommon - Reference: ekhtsu260ac - domestic hot water tank_daikin_lxwxh 600x695x1610 mm
Constraints - Elevation: 0 mm; Level: Level: Level 1; Host: Level : Level 1; TBQ_H Accessory_type: standard; TBQ_H Accessory position_Z: 0 mm; TBQ_H Logo LOD200: no; TBQ_H Logo LOD400: no; TBQ_H Offset from base level: 0 mm; TBQ_H Suspension_height: 0 mm; TBQ_H X: 300 mm; TBQ_H Y: 347.5 mm
Construction - TBQen_C_alignment_index: 0; TBQen_C_GOg: no; TBQen_C_offset_from_base_level: 0 mm; TBQen_C_SOg: yes; TBQen_C_alignment: Center; TBQen_C_suspension_height: 0 mm
Dimensions - Area: 62.9964 m2; Volume: 17.7778 m3
Graphics - TBQen_C_clearance_zone: no; TBQen_C_connection_zone: no; TBQen_C_logo: no; TBQen_C_maintenance_zone: no; TBQen_C_neighbour_unit: no; TBQen_C_neighbour_unit_displacement_back: 0 mm; TBQen_C_neighbour_unit_displacement_front: 0 mm; TBQen_C_neighbour_unit_displacement_left: 0 mm; TBQen_C_neighbour_unit_displacement_right: 0 mm
Identity Data - Mark: 90
Mechanical - RSen_P_c01_volume_flow: 0 m3/s; RSen_P_c02_volume_flow: 0 m3/s; RSen_P_c03_volume_flow: 0 m3/s; RSen_P_c04_volume_flow: 0 m3/s; RSen_P_c05_volume_flow: 0 m3/s; RSen_P_c06_volume_flow: 0 m3/s; RSen_P_c07_volume_flow: 0 m3/s; RSen_P_c08_volume_flow: 0 m3/s; System Classification: Hydronic Return,Hydronic Supply,Domestic Hot Water,Power,Controls,Hydronic Return,Domestic Cold Water,Hydronic Supply,Undefined
Other - Schedule Level: Level: Level 1; Family: RSen_53_ME_FB_domestic hot water tank_daikin: ekhtsu260ac - domestic hot water tank_daikin_lxwxh 600x695x1610 mm; Family and Type: RSen_53_ME_FB_domestic hot water tank_daikin: ekhtsu260ac - domestic hot water tank_daikin_lxwxh 600x695x1610 mm; Type: RSen_53_ME_FB_domestic hot water tank_daikin: ekhtsu260ac - domestic hot water tank_daikin_lxwxh 600x695x1610 mm; Type Id: RSen_53_ME_FB_domestic hot water tank_daikin: ekhtsu260ac - domestic hot water tank_daikin_lxwxh 600x695x1610 mm
Phasing - Phase Created: New Construction
Text - RSen_C_content_manual: https://thorbiq.freshdesk.com/support/solutions

# IfcWallStandardCase: Basic Wall:Wall 1 (2)
In: Level 1
Type - PredefinedType: STANDARD; Material: RSen_x_rgb 192 192 192 T00 silver_gen 200 mm
Type - Analytical Properties - Absorptance: 0.1; Roughness: 1
Type - Construction - Function: Exterior; Width: 200 mm; Wrapping at Inserts: Do not wrap
Type - Graphics - Coarse Scale Fill Color: 0
Type - Identity Data - Type Name: Wall 1
Type - Other - Category: Walls; Family Name: Basic Wall
Constraints - Base Constraint: Level: Level 1; Base Extension Distance: 0 mm; Base is Attached: no; Base Offset: 0 mm; Location Line: Wall Centerline; Related to Mass: no; Room Bounding: yes; Top Extension Distance: 0 mm; Top is Attached: no; Top Offset: 0 mm; Unconnected Height: 3000 mm
Other - Family: Basic Wall: Wall 1; Family and Type: Basic Wall: Wall 1; Type: Basic Wall: Wall 1; Type Id: Basic Wall: Wall 1
Phasing - Phase Created: New Construction
Structural - Enable Analytical Model: no; Structural: no; Structural Usage: Non-bearing
Pset_WallCommon - Reference: Wall 1; LoadBearing: no; ExtendToStructure: no; IsExternal: yes
Name (Basic Wall:Wall 1:...) | Area (m2) | Length (mm) | Volume (m3)
1430901 | 6.3 | 2000 | 1.26
1430902 | 69.0073 | 23102.4 | 13.8015
